# OpenTallas memory compiler (tools/mem_compiler), ASAP7 abstract view, track-aligned v2 (build_aligned_v2.py)
VERSION 5.7 ;
BUSBITCHARS "[]" ;
DIVIDERCHAR "/" ;
PROPERTYDEFINITIONS
  MACRO width INTEGER ;
  MACRO depth INTEGER ;
  MACRO banks INTEGER ;
END PROPERTYDEFINITIONS
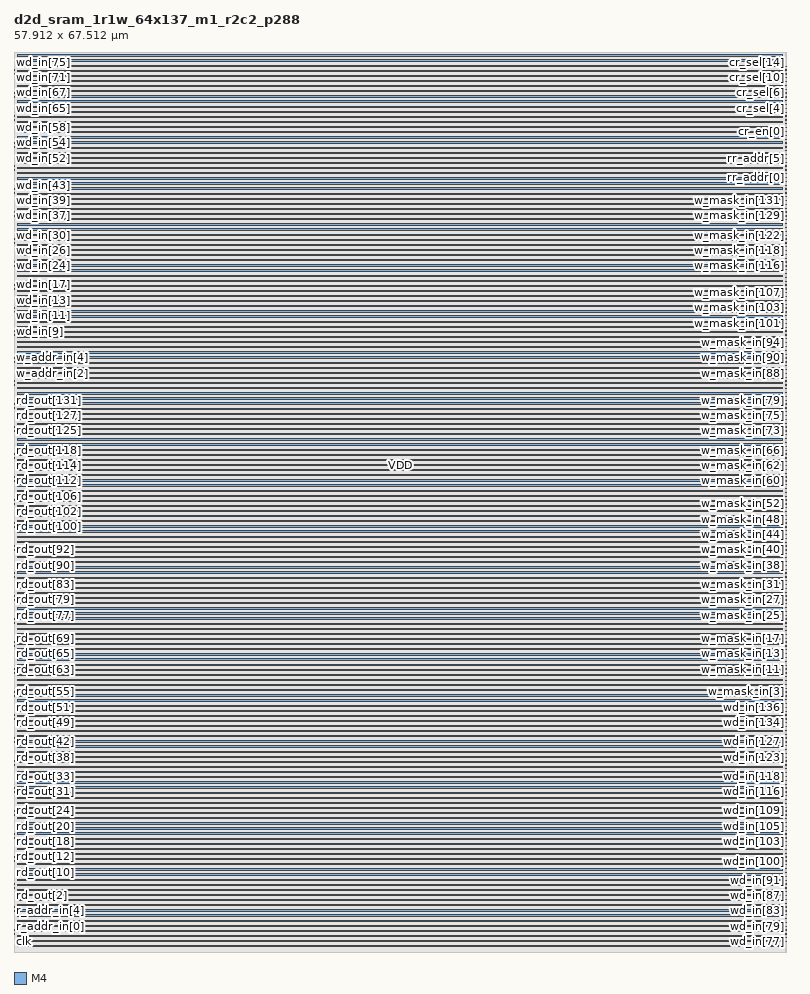
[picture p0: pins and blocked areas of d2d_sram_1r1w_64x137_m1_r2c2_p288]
MACRO d2d_sram_1r1w_64x137_m1_r2c2_p288
  PROPERTY width 137 ;
  PROPERTY depth 64 ;
  PROPERTY banks 1 ;
  FOREIGN d2d_sram_1r1w_64x137_m1_r2c2_p288 0 0 ;
  SYMMETRY X Y ;
  SIZE 57.912 BY 67.512 ;
  CLASS BLOCK ;
  PIN clk
    DIRECTION INPUT ;
    USE CLOCK ;
    SHAPE ABUTMENT ;
    PORT
      LAYER M4 ;
      RECT 0.000 0.768 0.024 0.792 ;
    END
  END clk
  PIN r_ce_in
    DIRECTION INPUT ;
    USE SIGNAL ;
    SHAPE ABUTMENT ;
    PORT
      LAYER M4 ;
      RECT 0.000 1.056 0.024 1.080 ;
    END
  END r_ce_in
  PIN r_addr_in[0]
    DIRECTION INPUT ;
    USE SIGNAL ;
    SHAPE ABUTMENT ;
    PORT
      LAYER M4 ;
      RECT 0.000 1.344 0.024 1.368 ;
    END
  END r_addr_in[0]
  PIN r_addr_in[1]
    DIRECTION INPUT ;
    USE SIGNAL ;
    SHAPE ABUTMENT ;
    PORT
      LAYER M4 ;
      RECT 0.000 1.632 0.024 1.656 ;
    END
  END r_addr_in[1]
  PIN r_addr_in[2]
    DIRECTION INPUT ;
    USE SIGNAL ;
    SHAPE ABUTMENT ;
    PORT
      LAYER M4 ;
      RECT 0.000 1.920 0.024 1.944 ;
    END
  END r_addr_in[2]
  PIN r_addr_in[3]
    DIRECTION INPUT ;
    USE SIGNAL ;
    SHAPE ABUTMENT ;
    PORT
      LAYER M4 ;
      RECT 0.000 2.208 0.024 2.232 ;
    END
  END r_addr_in[3]
  PIN r_addr_in[4]
    DIRECTION INPUT ;
    USE SIGNAL ;
    SHAPE ABUTMENT ;
    PORT
      LAYER M4 ;
      RECT 0.000 2.496 0.024 2.520 ;
    END
  END r_addr_in[4]
  PIN r_addr_in[5]
    DIRECTION INPUT ;
    USE SIGNAL ;
    SHAPE ABUTMENT ;
    PORT
      LAYER M4 ;
      RECT 0.000 2.784 0.024 2.808 ;
    END
  END r_addr_in[5]
  PIN rd_out[0]
    DIRECTION OUTPUT ;
    USE SIGNAL ;
    SHAPE ABUTMENT ;
    PORT
      LAYER M4 ;
      RECT 0.000 3.072 0.024 3.096 ;
    END
  END rd_out[0]
  PIN rd_out[1]
    DIRECTION OUTPUT ;
    USE SIGNAL ;
    SHAPE ABUTMENT ;
    PORT
      LAYER M4 ;
      RECT 0.000 3.360 0.024 3.384 ;
    END
  END rd_out[1]
  PIN rd_out[2]
    DIRECTION OUTPUT ;
    USE SIGNAL ;
    SHAPE ABUTMENT ;
    PORT
      LAYER M4 ;
      RECT 0.000 3.648 0.024 3.672 ;
    END
  END rd_out[2]
  PIN rd_out[3]
    DIRECTION OUTPUT ;
    USE SIGNAL ;
    SHAPE ABUTMENT ;
    PORT
      LAYER M4 ;
      RECT 0.000 3.936 0.024 3.960 ;
    END
  END rd_out[3]
  PIN rd_out[4]
    DIRECTION OUTPUT ;
    USE SIGNAL ;
    SHAPE ABUTMENT ;
    PORT
      LAYER M4 ;
      RECT 0.000 4.224 0.024 4.248 ;
    END
  END rd_out[4]
  PIN rd_out[5]
    DIRECTION OUTPUT ;
    USE SIGNAL ;
    SHAPE ABUTMENT ;
    PORT
      LAYER M4 ;
      RECT 0.000 4.512 0.024 4.536 ;
    END
  END rd_out[5]
  PIN rd_out[6]
    DIRECTION OUTPUT ;
    USE SIGNAL ;
    SHAPE ABUTMENT ;
    PORT
      LAYER M4 ;
      RECT 0.000 4.800 0.024 4.824 ;
    END
  END rd_out[6]
  PIN rd_out[7]
    DIRECTION OUTPUT ;
    USE SIGNAL ;
    SHAPE ABUTMENT ;
    PORT
      LAYER M4 ;
      RECT 0.000 5.088 0.024 5.112 ;
    END
  END rd_out[7]
  PIN rd_out[8]
    DIRECTION OUTPUT ;
    USE SIGNAL ;
    SHAPE ABUTMENT ;
    PORT
      LAYER M4 ;
      RECT 0.000 5.376 0.024 5.400 ;
    END
  END rd_out[8]
  PIN rd_out[9]
    DIRECTION OUTPUT ;
    USE SIGNAL ;
    SHAPE ABUTMENT ;
    PORT
      LAYER M4 ;
      RECT 0.000 5.664 0.024 5.688 ;
    END
  END rd_out[9]
  PIN rd_out[10]
    DIRECTION OUTPUT ;
    USE SIGNAL ;
    SHAPE ABUTMENT ;
    PORT
      LAYER M4 ;
      RECT 0.000 5.952 0.024 5.976 ;
    END
  END rd_out[10]
  PIN rd_out[11]
    DIRECTION OUTPUT ;
    USE SIGNAL ;
    SHAPE ABUTMENT ;
    PORT
      LAYER M4 ;
      RECT 0.000 6.240 0.024 6.264 ;
    END
  END rd_out[11]
  PIN rd_out[12]
    DIRECTION OUTPUT ;
    USE SIGNAL ;
    SHAPE ABUTMENT ;
    PORT
      LAYER M4 ;
      RECT 0.000 6.528 0.024 6.552 ;
    END
  END rd_out[12]
  PIN rd_out[13]
    DIRECTION OUTPUT ;
    USE SIGNAL ;
    SHAPE ABUTMENT ;
    PORT
      LAYER M4 ;
      RECT 0.000 6.816 0.024 6.840 ;
    END
  END rd_out[13]
  PIN rd_out[14]
    DIRECTION OUTPUT ;
    USE SIGNAL ;
    SHAPE ABUTMENT ;
    PORT
      LAYER M4 ;
      RECT 0.000 7.104 0.024 7.128 ;
    END
  END rd_out[14]
  PIN rd_out[15]
    DIRECTION OUTPUT ;
    USE SIGNAL ;
    SHAPE ABUTMENT ;
    PORT
      LAYER M4 ;
      RECT 0.000 7.392 0.024 7.416 ;
    END
  END rd_out[15]
  PIN rd_out[16]
    DIRECTION OUTPUT ;
    USE SIGNAL ;
    SHAPE ABUTMENT ;
    PORT
      LAYER M4 ;
      RECT 0.000 7.680 0.024 7.704 ;
    END
  END rd_out[16]
  PIN rd_out[17]
    DIRECTION OUTPUT ;
    USE SIGNAL ;
    SHAPE ABUTMENT ;
    PORT
      LAYER M4 ;
      RECT 0.000 7.968 0.024 7.992 ;
    END
  END rd_out[17]
  PIN rd_out[18]
    DIRECTION OUTPUT ;
    USE SIGNAL ;
    SHAPE ABUTMENT ;
    PORT
      LAYER M4 ;
      RECT 0.000 8.256 0.024 8.280 ;
    END
  END rd_out[18]
  PIN rd_out[19]
    DIRECTION OUTPUT ;
    USE SIGNAL ;
    SHAPE ABUTMENT ;
    PORT
      LAYER M4 ;
      RECT 0.000 8.544 0.024 8.568 ;
    END
  END rd_out[19]
  PIN rd_out[20]
    DIRECTION OUTPUT ;
    USE SIGNAL ;
    SHAPE ABUTMENT ;
    PORT
      LAYER M4 ;
      RECT 0.000 8.832 0.024 8.856 ;
    END
  END rd_out[20]
  PIN rd_out[21]
    DIRECTION OUTPUT ;
    USE SIGNAL ;
    SHAPE ABUTMENT ;
    PORT
      LAYER M4 ;
      RECT 0.000 9.120 0.024 9.144 ;
    END
  END rd_out[21]
  PIN rd_out[22]
    DIRECTION OUTPUT ;
    USE SIGNAL ;
    SHAPE ABUTMENT ;
    PORT
      LAYER M4 ;
      RECT 0.000 9.408 0.024 9.432 ;
    END
  END rd_out[22]
  PIN rd_out[23]
    DIRECTION OUTPUT ;
    USE SIGNAL ;
    SHAPE ABUTMENT ;
    PORT
      LAYER M4 ;
      RECT 0.000 9.696 0.024 9.720 ;
    END
  END rd_out[23]
  PIN rd_out[24]
    DIRECTION OUTPUT ;
    USE SIGNAL ;
    SHAPE ABUTMENT ;
    PORT
      LAYER M4 ;
      RECT 0.000 9.984 0.024 10.008 ;
    END
  END rd_out[24]
  PIN rd_out[25]
    DIRECTION OUTPUT ;
    USE SIGNAL ;
    SHAPE ABUTMENT ;
    PORT
      LAYER M4 ;
      RECT 0.000 10.272 0.024 10.296 ;
    END
  END rd_out[25]
  PIN rd_out[26]
    DIRECTION OUTPUT ;
    USE SIGNAL ;
    SHAPE ABUTMENT ;
    PORT
      LAYER M4 ;
      RECT 0.000 10.560 0.024 10.584 ;
    END
  END rd_out[26]
  PIN rd_out[27]
    DIRECTION OUTPUT ;
    USE SIGNAL ;
    SHAPE ABUTMENT ;
    PORT
      LAYER M4 ;
      RECT 0.000 10.848 0.024 10.872 ;
    END
  END rd_out[27]
  PIN rd_out[28]
    DIRECTION OUTPUT ;
    USE SIGNAL ;
    SHAPE ABUTMENT ;
    PORT
      LAYER M4 ;
      RECT 0.000 11.136 0.024 11.160 ;
    END
  END rd_out[28]
  PIN rd_out[29]
    DIRECTION OUTPUT ;
    USE SIGNAL ;
    SHAPE ABUTMENT ;
    PORT
      LAYER M4 ;
      RECT 0.000 11.424 0.024 11.448 ;
    END
  END rd_out[29]
  PIN rd_out[30]
    DIRECTION OUTPUT ;
    USE SIGNAL ;
    SHAPE ABUTMENT ;
    PORT
      LAYER M4 ;
      RECT 0.000 11.712 0.024 11.736 ;
    END
  END rd_out[30]
  PIN rd_out[31]
    DIRECTION OUTPUT ;
    USE SIGNAL ;
    SHAPE ABUTMENT ;
    PORT
      LAYER M4 ;
      RECT 0.000 12.000 0.024 12.024 ;
    END
  END rd_out[31]
  PIN rd_out[32]
    DIRECTION OUTPUT ;
    USE SIGNAL ;
    SHAPE ABUTMENT ;
    PORT
      LAYER M4 ;
      RECT 0.000 12.288 0.024 12.312 ;
    END
  END rd_out[32]
  PIN rd_out[33]
    DIRECTION OUTPUT ;
    USE SIGNAL ;
    SHAPE ABUTMENT ;
    PORT
      LAYER M4 ;
      RECT 0.000 12.576 0.024 12.600 ;
    END
  END rd_out[33]
  PIN rd_out[34]
    DIRECTION OUTPUT ;
    USE SIGNAL ;
    SHAPE ABUTMENT ;
    PORT
      LAYER M4 ;
      RECT 0.000 12.864 0.024 12.888 ;
    END
  END rd_out[34]
  PIN rd_out[35]
    DIRECTION OUTPUT ;
    USE SIGNAL ;
    SHAPE ABUTMENT ;
    PORT
      LAYER M4 ;
      RECT 0.000 13.152 0.024 13.176 ;
    END
  END rd_out[35]
  PIN rd_out[36]
    DIRECTION OUTPUT ;
    USE SIGNAL ;
    SHAPE ABUTMENT ;
    PORT
      LAYER M4 ;
      RECT 0.000 13.440 0.024 13.464 ;
    END
  END rd_out[36]
  PIN rd_out[37]
    DIRECTION OUTPUT ;
    USE SIGNAL ;
    SHAPE ABUTMENT ;
    PORT
      LAYER M4 ;
      RECT 0.000 13.728 0.024 13.752 ;
    END
  END rd_out[37]
  PIN rd_out[38]
    DIRECTION OUTPUT ;
    USE SIGNAL ;
    SHAPE ABUTMENT ;
    PORT
      LAYER M4 ;
      RECT 0.000 14.016 0.024 14.040 ;
    END
  END rd_out[38]
  PIN rd_out[39]
    DIRECTION OUTPUT ;
    USE SIGNAL ;
    SHAPE ABUTMENT ;
    PORT
      LAYER M4 ;
      RECT 0.000 14.304 0.024 14.328 ;
    END
  END rd_out[39]
  PIN rd_out[40]
    DIRECTION OUTPUT ;
    USE SIGNAL ;
    SHAPE ABUTMENT ;
    PORT
      LAYER M4 ;
      RECT 0.000 14.592 0.024 14.616 ;
    END
  END rd_out[40]
  PIN rd_out[41]
    DIRECTION OUTPUT ;
    USE SIGNAL ;
    SHAPE ABUTMENT ;
    PORT
      LAYER M4 ;
      RECT 0.000 14.880 0.024 14.904 ;
    END
  END rd_out[41]
  PIN rd_out[42]
    DIRECTION OUTPUT ;
    USE SIGNAL ;
    SHAPE ABUTMENT ;
    PORT
      LAYER M4 ;
      RECT 0.000 15.168 0.024 15.192 ;
    END
  END rd_out[42]
  PIN rd_out[43]
    DIRECTION OUTPUT ;
    USE SIGNAL ;
    SHAPE ABUTMENT ;
    PORT
      LAYER M4 ;
      RECT 0.000 15.456 0.024 15.480 ;
    END
  END rd_out[43]
  PIN rd_out[44]
    DIRECTION OUTPUT ;
    USE SIGNAL ;
    SHAPE ABUTMENT ;
    PORT
      LAYER M4 ;
      RECT 0.000 15.744 0.024 15.768 ;
    END
  END rd_out[44]
  PIN rd_out[45]
    DIRECTION OUTPUT ;
    USE SIGNAL ;
    SHAPE ABUTMENT ;
    PORT
      LAYER M4 ;
      RECT 0.000 16.032 0.024 16.056 ;
    END
  END rd_out[45]
  PIN rd_out[46]
    DIRECTION OUTPUT ;
    USE SIGNAL ;
    SHAPE ABUTMENT ;
    PORT
      LAYER M4 ;
      RECT 0.000 16.320 0.024 16.344 ;
    END
  END rd_out[46]
  PIN rd_out[47]
    DIRECTION OUTPUT ;
    USE SIGNAL ;
    SHAPE ABUTMENT ;
    PORT
      LAYER M4 ;
      RECT 0.000 16.608 0.024 16.632 ;
    END
  END rd_out[47]
  PIN rd_out[48]
    DIRECTION OUTPUT ;
    USE SIGNAL ;
    SHAPE ABUTMENT ;
    PORT
      LAYER M4 ;
      RECT 0.000 16.896 0.024 16.920 ;
    END
  END rd_out[48]
  PIN rd_out[49]
    DIRECTION OUTPUT ;
    USE SIGNAL ;
    SHAPE ABUTMENT ;
    PORT
      LAYER M4 ;
      RECT 0.000 17.184 0.024 17.208 ;
    END
  END rd_out[49]
  PIN rd_out[50]
    DIRECTION OUTPUT ;
    USE SIGNAL ;
    SHAPE ABUTMENT ;
    PORT
      LAYER M4 ;
      RECT 0.000 17.472 0.024 17.496 ;
    END
  END rd_out[50]
  PIN rd_out[51]
    DIRECTION OUTPUT ;
    USE SIGNAL ;
    SHAPE ABUTMENT ;
    PORT
      LAYER M4 ;
      RECT 0.000 17.760 0.024 17.784 ;
    END
  END rd_out[51]
  PIN rd_out[52]
    DIRECTION OUTPUT ;
    USE SIGNAL ;
    SHAPE ABUTMENT ;
    PORT
      LAYER M4 ;
      RECT 0.000 18.048 0.024 18.072 ;
    END
  END rd_out[52]
  PIN rd_out[53]
    DIRECTION OUTPUT ;
    USE SIGNAL ;
    SHAPE ABUTMENT ;
    PORT
      LAYER M4 ;
      RECT 0.000 18.336 0.024 18.360 ;
    END
  END rd_out[53]
  PIN rd_out[54]
    DIRECTION OUTPUT ;
    USE SIGNAL ;
    SHAPE ABUTMENT ;
    PORT
      LAYER M4 ;
      RECT 0.000 18.624 0.024 18.648 ;
    END
  END rd_out[54]
  PIN rd_out[55]
    DIRECTION OUTPUT ;
    USE SIGNAL ;
    SHAPE ABUTMENT ;
    PORT
      LAYER M4 ;
      RECT 0.000 18.912 0.024 18.936 ;
    END
  END rd_out[55]
  PIN rd_out[56]
    DIRECTION OUTPUT ;
    USE SIGNAL ;
    SHAPE ABUTMENT ;
    PORT
      LAYER M4 ;
      RECT 0.000 19.200 0.024 19.224 ;
    END
  END rd_out[56]
  PIN rd_out[57]
    DIRECTION OUTPUT ;
    USE SIGNAL ;
    SHAPE ABUTMENT ;
    PORT
      LAYER M4 ;
      RECT 0.000 19.488 0.024 19.512 ;
    END
  END rd_out[57]
  PIN rd_out[58]
    DIRECTION OUTPUT ;
    USE SIGNAL ;
    SHAPE ABUTMENT ;
    PORT
      LAYER M4 ;
      RECT 0.000 19.776 0.024 19.800 ;
    END
  END rd_out[58]
  PIN rd_out[59]
    DIRECTION OUTPUT ;
    USE SIGNAL ;
    SHAPE ABUTMENT ;
    PORT
      LAYER M4 ;
      RECT 0.000 20.064 0.024 20.088 ;
    END
  END rd_out[59]
  PIN rd_out[60]
    DIRECTION OUTPUT ;
    USE SIGNAL ;
    SHAPE ABUTMENT ;
    PORT
      LAYER M4 ;
      RECT 0.000 20.352 0.024 20.376 ;
    END
  END rd_out[60]
  PIN rd_out[61]
    DIRECTION OUTPUT ;
    USE SIGNAL ;
    SHAPE ABUTMENT ;
    PORT
      LAYER M4 ;
      RECT 0.000 20.640 0.024 20.664 ;
    END
  END rd_out[61]
  PIN rd_out[62]
    DIRECTION OUTPUT ;
    USE SIGNAL ;
    SHAPE ABUTMENT ;
    PORT
      LAYER M4 ;
      RECT 0.000 20.928 0.024 20.952 ;
    END
  END rd_out[62]
  PIN rd_out[63]
    DIRECTION OUTPUT ;
    USE SIGNAL ;
    SHAPE ABUTMENT ;
    PORT
      LAYER M4 ;
      RECT 0.000 21.216 0.024 21.240 ;
    END
  END rd_out[63]
  PIN rd_out[64]
    DIRECTION OUTPUT ;
    USE SIGNAL ;
    SHAPE ABUTMENT ;
    PORT
      LAYER M4 ;
      RECT 0.000 21.504 0.024 21.528 ;
    END
  END rd_out[64]
  PIN rd_out[65]
    DIRECTION OUTPUT ;
    USE SIGNAL ;
    SHAPE ABUTMENT ;
    PORT
      LAYER M4 ;
      RECT 0.000 21.792 0.024 21.816 ;
    END
  END rd_out[65]
  PIN rd_out[66]
    DIRECTION OUTPUT ;
    USE SIGNAL ;
    SHAPE ABUTMENT ;
    PORT
      LAYER M4 ;
      RECT 0.000 22.080 0.024 22.104 ;
    END
  END rd_out[66]
  PIN rd_out[67]
    DIRECTION OUTPUT ;
    USE SIGNAL ;
    SHAPE ABUTMENT ;
    PORT
      LAYER M4 ;
      RECT 0.000 22.368 0.024 22.392 ;
    END
  END rd_out[67]
  PIN rd_out[68]
    DIRECTION OUTPUT ;
    USE SIGNAL ;
    SHAPE ABUTMENT ;
    PORT
      LAYER M4 ;
      RECT 0.000 22.656 0.024 22.680 ;
    END
  END rd_out[68]
  PIN rd_out[69]
    DIRECTION OUTPUT ;
    USE SIGNAL ;
    SHAPE ABUTMENT ;
    PORT
      LAYER M4 ;
      RECT 0.000 22.944 0.024 22.968 ;
    END
  END rd_out[69]
  PIN rd_out[70]
    DIRECTION OUTPUT ;
    USE SIGNAL ;
    SHAPE ABUTMENT ;
    PORT
      LAYER M4 ;
      RECT 0.000 23.232 0.024 23.256 ;
    END
  END rd_out[70]
  PIN rd_out[71]
    DIRECTION OUTPUT ;
    USE SIGNAL ;
    SHAPE ABUTMENT ;
    PORT
      LAYER M4 ;
      RECT 0.000 23.520 0.024 23.544 ;
    END
  END rd_out[71]
  PIN rd_out[72]
    DIRECTION OUTPUT ;
    USE SIGNAL ;
    SHAPE ABUTMENT ;
    PORT
      LAYER M4 ;
      RECT 0.000 23.808 0.024 23.832 ;
    END
  END rd_out[72]
  PIN rd_out[73]
    DIRECTION OUTPUT ;
    USE SIGNAL ;
    SHAPE ABUTMENT ;
    PORT
      LAYER M4 ;
      RECT 0.000 24.096 0.024 24.120 ;
    END
  END rd_out[73]
  PIN rd_out[74]
    DIRECTION OUTPUT ;
    USE SIGNAL ;
    SHAPE ABUTMENT ;
    PORT
      LAYER M4 ;
      RECT 0.000 24.384 0.024 24.408 ;
    END
  END rd_out[74]
  PIN rd_out[75]
    DIRECTION OUTPUT ;
    USE SIGNAL ;
    SHAPE ABUTMENT ;
    PORT
      LAYER M4 ;
      RECT 0.000 24.672 0.024 24.696 ;
    END
  END rd_out[75]
  PIN rd_out[76]
    DIRECTION OUTPUT ;
    USE SIGNAL ;
    SHAPE ABUTMENT ;
    PORT
      LAYER M4 ;
      RECT 0.000 24.960 0.024 24.984 ;
    END
  END rd_out[76]
  PIN rd_out[77]
    DIRECTION OUTPUT ;
    USE SIGNAL ;
    SHAPE ABUTMENT ;
    PORT
      LAYER M4 ;
      RECT 0.000 25.248 0.024 25.272 ;
    END
  END rd_out[77]
  PIN rd_out[78]
    DIRECTION OUTPUT ;
    USE SIGNAL ;
    SHAPE ABUTMENT ;
    PORT
      LAYER M4 ;
      RECT 0.000 25.536 0.024 25.560 ;
    END
  END rd_out[78]
  PIN rd_out[79]
    DIRECTION OUTPUT ;
    USE SIGNAL ;
    SHAPE ABUTMENT ;
    PORT
      LAYER M4 ;
      RECT 0.000 25.824 0.024 25.848 ;
    END
  END rd_out[79]
  PIN rd_out[80]
    DIRECTION OUTPUT ;
    USE SIGNAL ;
    SHAPE ABUTMENT ;
    PORT
      LAYER M4 ;
      RECT 0.000 26.112 0.024 26.136 ;
    END
  END rd_out[80]
  PIN rd_out[81]
    DIRECTION OUTPUT ;
    USE SIGNAL ;
    SHAPE ABUTMENT ;
    PORT
      LAYER M4 ;
      RECT 0.000 26.400 0.024 26.424 ;
    END
  END rd_out[81]
  PIN rd_out[82]
    DIRECTION OUTPUT ;
    USE SIGNAL ;
    SHAPE ABUTMENT ;
    PORT
      LAYER M4 ;
      RECT 0.000 26.688 0.024 26.712 ;
    END
  END rd_out[82]
  PIN rd_out[83]
    DIRECTION OUTPUT ;
    USE SIGNAL ;
    SHAPE ABUTMENT ;
    PORT
      LAYER M4 ;
      RECT 0.000 26.976 0.024 27.000 ;
    END
  END rd_out[83]
  PIN rd_out[84]
    DIRECTION OUTPUT ;
    USE SIGNAL ;
    SHAPE ABUTMENT ;
    PORT
      LAYER M4 ;
      RECT 0.000 27.264 0.024 27.288 ;
    END
  END rd_out[84]
  PIN rd_out[85]
    DIRECTION OUTPUT ;
    USE SIGNAL ;
    SHAPE ABUTMENT ;
    PORT
      LAYER M4 ;
      RECT 0.000 27.552 0.024 27.576 ;
    END
  END rd_out[85]
  PIN rd_out[86]
    DIRECTION OUTPUT ;
    USE SIGNAL ;
    SHAPE ABUTMENT ;
    PORT
      LAYER M4 ;
      RECT 0.000 27.840 0.024 27.864 ;
    END
  END rd_out[86]
  PIN rd_out[87]
    DIRECTION OUTPUT ;
    USE SIGNAL ;
    SHAPE ABUTMENT ;
    PORT
      LAYER M4 ;
      RECT 0.000 28.128 0.024 28.152 ;
    END
  END rd_out[87]
  PIN rd_out[88]
    DIRECTION OUTPUT ;
    USE SIGNAL ;
    SHAPE ABUTMENT ;
    PORT
      LAYER M4 ;
      RECT 0.000 28.416 0.024 28.440 ;
    END
  END rd_out[88]
  PIN rd_out[89]
    DIRECTION OUTPUT ;
    USE SIGNAL ;
    SHAPE ABUTMENT ;
    PORT
      LAYER M4 ;
      RECT 0.000 28.704 0.024 28.728 ;
    END
  END rd_out[89]
  PIN rd_out[90]
    DIRECTION OUTPUT ;
    USE SIGNAL ;
    SHAPE ABUTMENT ;
    PORT
      LAYER M4 ;
      RECT 0.000 28.992 0.024 29.016 ;
    END
  END rd_out[90]
  PIN rd_out[91]
    DIRECTION OUTPUT ;
    USE SIGNAL ;
    SHAPE ABUTMENT ;
    PORT
      LAYER M4 ;
      RECT 0.000 29.280 0.024 29.304 ;
    END
  END rd_out[91]
  PIN rd_out[92]
    DIRECTION OUTPUT ;
    USE SIGNAL ;
    SHAPE ABUTMENT ;
    PORT
      LAYER M4 ;
      RECT 0.000 29.568 0.024 29.592 ;
    END
  END rd_out[92]
  PIN rd_out[93]
    DIRECTION OUTPUT ;
    USE SIGNAL ;
    SHAPE ABUTMENT ;
    PORT
      LAYER M4 ;
      RECT 0.000 29.856 0.024 29.880 ;
    END
  END rd_out[93]
  PIN rd_out[94]
    DIRECTION OUTPUT ;
    USE SIGNAL ;
    SHAPE ABUTMENT ;
    PORT
      LAYER M4 ;
      RECT 0.000 30.144 0.024 30.168 ;
    END
  END rd_out[94]
  PIN rd_out[95]
    DIRECTION OUTPUT ;
    USE SIGNAL ;
    SHAPE ABUTMENT ;
    PORT
      LAYER M4 ;
      RECT 0.000 30.432 0.024 30.456 ;
    END
  END rd_out[95]
  PIN rd_out[96]
    DIRECTION OUTPUT ;
    USE SIGNAL ;
    SHAPE ABUTMENT ;
    PORT
      LAYER M4 ;
      RECT 0.000 30.720 0.024 30.744 ;
    END
  END rd_out[96]
  PIN rd_out[97]
    DIRECTION OUTPUT ;
    USE SIGNAL ;
    SHAPE ABUTMENT ;
    PORT
      LAYER M4 ;
      RECT 0.000 31.008 0.024 31.032 ;
    END
  END rd_out[97]
  PIN rd_out[98]
    DIRECTION OUTPUT ;
    USE SIGNAL ;
    SHAPE ABUTMENT ;
    PORT
      LAYER M4 ;
      RECT 0.000 31.296 0.024 31.320 ;
    END
  END rd_out[98]
  PIN rd_out[99]
    DIRECTION OUTPUT ;
    USE SIGNAL ;
    SHAPE ABUTMENT ;
    PORT
      LAYER M4 ;
      RECT 0.000 31.584 0.024 31.608 ;
    END
  END rd_out[99]
  PIN rd_out[100]
    DIRECTION OUTPUT ;
    USE SIGNAL ;
    SHAPE ABUTMENT ;
    PORT
      LAYER M4 ;
      RECT 0.000 31.872 0.024 31.896 ;
    END
  END rd_out[100]
  PIN rd_out[101]
    DIRECTION OUTPUT ;
    USE SIGNAL ;
    SHAPE ABUTMENT ;
    PORT
      LAYER M4 ;
      RECT 0.000 32.160 0.024 32.184 ;
    END
  END rd_out[101]
  PIN rd_out[102]
    DIRECTION OUTPUT ;
    USE SIGNAL ;
    SHAPE ABUTMENT ;
    PORT
      LAYER M4 ;
      RECT 0.000 32.448 0.024 32.472 ;
    END
  END rd_out[102]
  PIN rd_out[103]
    DIRECTION OUTPUT ;
    USE SIGNAL ;
    SHAPE ABUTMENT ;
    PORT
      LAYER M4 ;
      RECT 0.000 32.736 0.024 32.760 ;
    END
  END rd_out[103]
  PIN rd_out[104]
    DIRECTION OUTPUT ;
    USE SIGNAL ;
    SHAPE ABUTMENT ;
    PORT
      LAYER M4 ;
      RECT 0.000 33.024 0.024 33.048 ;
    END
  END rd_out[104]
  PIN rd_out[105]
    DIRECTION OUTPUT ;
    USE SIGNAL ;
    SHAPE ABUTMENT ;
    PORT
      LAYER M4 ;
      RECT 0.000 33.312 0.024 33.336 ;
    END
  END rd_out[105]
  PIN rd_out[106]
    DIRECTION OUTPUT ;
    USE SIGNAL ;
    SHAPE ABUTMENT ;
    PORT
      LAYER M4 ;
      RECT 0.000 33.600 0.024 33.624 ;
    END
  END rd_out[106]
  PIN rd_out[107]
    DIRECTION OUTPUT ;
    USE SIGNAL ;
    SHAPE ABUTMENT ;
    PORT
      LAYER M4 ;
      RECT 0.000 33.888 0.024 33.912 ;
    END
  END rd_out[107]
  PIN rd_out[108]
    DIRECTION OUTPUT ;
    USE SIGNAL ;
    SHAPE ABUTMENT ;
    PORT
      LAYER M4 ;
      RECT 0.000 34.176 0.024 34.200 ;
    END
  END rd_out[108]
  PIN rd_out[109]
    DIRECTION OUTPUT ;
    USE SIGNAL ;
    SHAPE ABUTMENT ;
    PORT
      LAYER M4 ;
      RECT 0.000 34.464 0.024 34.488 ;
    END
  END rd_out[109]
  PIN rd_out[110]
    DIRECTION OUTPUT ;
    USE SIGNAL ;
    SHAPE ABUTMENT ;
    PORT
      LAYER M4 ;
      RECT 0.000 34.752 0.024 34.776 ;
    END
  END rd_out[110]
  PIN rd_out[111]
    DIRECTION OUTPUT ;
    USE SIGNAL ;
    SHAPE ABUTMENT ;
    PORT
      LAYER M4 ;
      RECT 0.000 35.040 0.024 35.064 ;
    END
  END rd_out[111]
  PIN rd_out[112]
    DIRECTION OUTPUT ;
    USE SIGNAL ;
    SHAPE ABUTMENT ;
    PORT
      LAYER M4 ;
      RECT 0.000 35.328 0.024 35.352 ;
    END
  END rd_out[112]
  PIN rd_out[113]
    DIRECTION OUTPUT ;
    USE SIGNAL ;
    SHAPE ABUTMENT ;
    PORT
      LAYER M4 ;
      RECT 0.000 35.616 0.024 35.640 ;
    END
  END rd_out[113]
  PIN rd_out[114]
    DIRECTION OUTPUT ;
    USE SIGNAL ;
    SHAPE ABUTMENT ;
    PORT
      LAYER M4 ;
      RECT 0.000 35.904 0.024 35.928 ;
    END
  END rd_out[114]
  PIN rd_out[115]
    DIRECTION OUTPUT ;
    USE SIGNAL ;
    SHAPE ABUTMENT ;
    PORT
      LAYER M4 ;
      RECT 0.000 36.192 0.024 36.216 ;
    END
  END rd_out[115]
  PIN rd_out[116]
    DIRECTION OUTPUT ;
    USE SIGNAL ;
    SHAPE ABUTMENT ;
    PORT
      LAYER M4 ;
      RECT 0.000 36.480 0.024 36.504 ;
    END
  END rd_out[116]
  PIN rd_out[117]
    DIRECTION OUTPUT ;
    USE SIGNAL ;
    SHAPE ABUTMENT ;
    PORT
      LAYER M4 ;
      RECT 0.000 36.768 0.024 36.792 ;
    END
  END rd_out[117]
  PIN rd_out[118]
    DIRECTION OUTPUT ;
    USE SIGNAL ;
    SHAPE ABUTMENT ;
    PORT
      LAYER M4 ;
      RECT 0.000 37.056 0.024 37.080 ;
    END
  END rd_out[118]
  PIN rd_out[119]
    DIRECTION OUTPUT ;
    USE SIGNAL ;
    SHAPE ABUTMENT ;
    PORT
      LAYER M4 ;
      RECT 0.000 37.344 0.024 37.368 ;
    END
  END rd_out[119]
  PIN rd_out[120]
    DIRECTION OUTPUT ;
    USE SIGNAL ;
    SHAPE ABUTMENT ;
    PORT
      LAYER M4 ;
      RECT 0.000 37.632 0.024 37.656 ;
    END
  END rd_out[120]
  PIN rd_out[121]
    DIRECTION OUTPUT ;
    USE SIGNAL ;
    SHAPE ABUTMENT ;
    PORT
      LAYER M4 ;
      RECT 0.000 37.920 0.024 37.944 ;
    END
  END rd_out[121]
  PIN rd_out[122]
    DIRECTION OUTPUT ;
    USE SIGNAL ;
    SHAPE ABUTMENT ;
    PORT
      LAYER M4 ;
      RECT 0.000 38.208 0.024 38.232 ;
    END
  END rd_out[122]
  PIN rd_out[123]
    DIRECTION OUTPUT ;
    USE SIGNAL ;
    SHAPE ABUTMENT ;
    PORT
      LAYER M4 ;
      RECT 0.000 38.496 0.024 38.520 ;
    END
  END rd_out[123]
  PIN rd_out[124]
    DIRECTION OUTPUT ;
    USE SIGNAL ;
    SHAPE ABUTMENT ;
    PORT
      LAYER M4 ;
      RECT 0.000 38.784 0.024 38.808 ;
    END
  END rd_out[124]
  PIN rd_out[125]
    DIRECTION OUTPUT ;
    USE SIGNAL ;
    SHAPE ABUTMENT ;
    PORT
      LAYER M4 ;
      RECT 0.000 39.072 0.024 39.096 ;
    END
  END rd_out[125]
  PIN rd_out[126]
    DIRECTION OUTPUT ;
    USE SIGNAL ;
    SHAPE ABUTMENT ;
    PORT
      LAYER M4 ;
      RECT 0.000 39.360 0.024 39.384 ;
    END
  END rd_out[126]
  PIN rd_out[127]
    DIRECTION OUTPUT ;
    USE SIGNAL ;
    SHAPE ABUTMENT ;
    PORT
      LAYER M4 ;
      RECT 0.000 39.648 0.024 39.672 ;
    END
  END rd_out[127]
  PIN rd_out[128]
    DIRECTION OUTPUT ;
    USE SIGNAL ;
    SHAPE ABUTMENT ;
    PORT
      LAYER M4 ;
      RECT 0.000 39.936 0.024 39.960 ;
    END
  END rd_out[128]
  PIN rd_out[129]
    DIRECTION OUTPUT ;
    USE SIGNAL ;
    SHAPE ABUTMENT ;
    PORT
      LAYER M4 ;
      RECT 0.000 40.224 0.024 40.248 ;
    END
  END rd_out[129]
  PIN rd_out[130]
    DIRECTION OUTPUT ;
    USE SIGNAL ;
    SHAPE ABUTMENT ;
    PORT
      LAYER M4 ;
      RECT 0.000 40.512 0.024 40.536 ;
    END
  END rd_out[130]
  PIN rd_out[131]
    DIRECTION OUTPUT ;
    USE SIGNAL ;
    SHAPE ABUTMENT ;
    PORT
      LAYER M4 ;
      RECT 0.000 40.800 0.024 40.824 ;
    END
  END rd_out[131]
  PIN rd_out[132]
    DIRECTION OUTPUT ;
    USE SIGNAL ;
    SHAPE ABUTMENT ;
    PORT
      LAYER M4 ;
      RECT 0.000 41.088 0.024 41.112 ;
    END
  END rd_out[132]
  PIN rd_out[133]
    DIRECTION OUTPUT ;
    USE SIGNAL ;
    SHAPE ABUTMENT ;
    PORT
      LAYER M4 ;
      RECT 0.000 41.376 0.024 41.400 ;
    END
  END rd_out[133]
  PIN rd_out[134]
    DIRECTION OUTPUT ;
    USE SIGNAL ;
    SHAPE ABUTMENT ;
    PORT
      LAYER M4 ;
      RECT 0.000 41.664 0.024 41.688 ;
    END
  END rd_out[134]
  PIN rd_out[135]
    DIRECTION OUTPUT ;
    USE SIGNAL ;
    SHAPE ABUTMENT ;
    PORT
      LAYER M4 ;
      RECT 0.000 41.952 0.024 41.976 ;
    END
  END rd_out[135]
  PIN rd_out[136]
    DIRECTION OUTPUT ;
    USE SIGNAL ;
    SHAPE ABUTMENT ;
    PORT
      LAYER M4 ;
      RECT 0.000 42.240 0.024 42.264 ;
    END
  END rd_out[136]
  PIN w_ce_in
    DIRECTION INPUT ;
    USE SIGNAL ;
    SHAPE ABUTMENT ;
    PORT
      LAYER M4 ;
      RECT 0.000 42.528 0.024 42.552 ;
    END
  END w_ce_in
  PIN w_addr_in[0]
    DIRECTION INPUT ;
    USE SIGNAL ;
    SHAPE ABUTMENT ;
    PORT
      LAYER M4 ;
      RECT 0.000 42.816 0.024 42.840 ;
    END
  END w_addr_in[0]
  PIN w_addr_in[1]
    DIRECTION INPUT ;
    USE SIGNAL ;
    SHAPE ABUTMENT ;
    PORT
      LAYER M4 ;
      RECT 0.000 43.104 0.024 43.128 ;
    END
  END w_addr_in[1]
  PIN w_addr_in[2]
    DIRECTION INPUT ;
    USE SIGNAL ;
    SHAPE ABUTMENT ;
    PORT
      LAYER M4 ;
      RECT 0.000 43.392 0.024 43.416 ;
    END
  END w_addr_in[2]
  PIN w_addr_in[3]
    DIRECTION INPUT ;
    USE SIGNAL ;
    SHAPE ABUTMENT ;
    PORT
      LAYER M4 ;
      RECT 0.000 43.680 0.024 43.704 ;
    END
  END w_addr_in[3]
  PIN w_addr_in[4]
    DIRECTION INPUT ;
    USE SIGNAL ;
    SHAPE ABUTMENT ;
    PORT
      LAYER M4 ;
      RECT 0.000 43.968 0.024 43.992 ;
    END
  END w_addr_in[4]
  PIN w_addr_in[5]
    DIRECTION INPUT ;
    USE SIGNAL ;
    SHAPE ABUTMENT ;
    PORT
      LAYER M4 ;
      RECT 0.000 44.256 0.024 44.280 ;
    END
  END w_addr_in[5]
  PIN wd_in[0]
    DIRECTION INPUT ;
    USE SIGNAL ;
    SHAPE ABUTMENT ;
    PORT
      LAYER M4 ;
      RECT 0.000 44.544 0.024 44.568 ;
    END
  END wd_in[0]
  PIN wd_in[1]
    DIRECTION INPUT ;
    USE SIGNAL ;
    SHAPE ABUTMENT ;
    PORT
      LAYER M4 ;
      RECT 0.000 44.832 0.024 44.856 ;
    END
  END wd_in[1]
  PIN wd_in[2]
    DIRECTION INPUT ;
    USE SIGNAL ;
    SHAPE ABUTMENT ;
    PORT
      LAYER M4 ;
      RECT 0.000 45.120 0.024 45.144 ;
    END
  END wd_in[2]
  PIN wd_in[3]
    DIRECTION INPUT ;
    USE SIGNAL ;
    SHAPE ABUTMENT ;
    PORT
      LAYER M4 ;
      RECT 0.000 45.408 0.024 45.432 ;
    END
  END wd_in[3]
  PIN wd_in[4]
    DIRECTION INPUT ;
    USE SIGNAL ;
    SHAPE ABUTMENT ;
    PORT
      LAYER M4 ;
      RECT 0.000 45.696 0.024 45.720 ;
    END
  END wd_in[4]
  PIN wd_in[5]
    DIRECTION INPUT ;
    USE SIGNAL ;
    SHAPE ABUTMENT ;
    PORT
      LAYER M4 ;
      RECT 0.000 45.984 0.024 46.008 ;
    END
  END wd_in[5]
  PIN wd_in[6]
    DIRECTION INPUT ;
    USE SIGNAL ;
    SHAPE ABUTMENT ;
    PORT
      LAYER M4 ;
      RECT 0.000 46.272 0.024 46.296 ;
    END
  END wd_in[6]
  PIN wd_in[7]
    DIRECTION INPUT ;
    USE SIGNAL ;
    SHAPE ABUTMENT ;
    PORT
      LAYER M4 ;
      RECT 0.000 46.560 0.024 46.584 ;
    END
  END wd_in[7]
  PIN wd_in[8]
    DIRECTION INPUT ;
    USE SIGNAL ;
    SHAPE ABUTMENT ;
    PORT
      LAYER M4 ;
      RECT 0.000 46.848 0.024 46.872 ;
    END
  END wd_in[8]
  PIN wd_in[9]
    DIRECTION INPUT ;
    USE SIGNAL ;
    SHAPE ABUTMENT ;
    PORT
      LAYER M4 ;
      RECT 0.000 47.136 0.024 47.160 ;
    END
  END wd_in[9]
  PIN wd_in[10]
    DIRECTION INPUT ;
    USE SIGNAL ;
    SHAPE ABUTMENT ;
    PORT
      LAYER M4 ;
      RECT 0.000 47.424 0.024 47.448 ;
    END
  END wd_in[10]
  PIN wd_in[11]
    DIRECTION INPUT ;
    USE SIGNAL ;
    SHAPE ABUTMENT ;
    PORT
      LAYER M4 ;
      RECT 0.000 47.712 0.024 47.736 ;
    END
  END wd_in[11]
  PIN wd_in[12]
    DIRECTION INPUT ;
    USE SIGNAL ;
    SHAPE ABUTMENT ;
    PORT
      LAYER M4 ;
      RECT 0.000 48.000 0.024 48.024 ;
    END
  END wd_in[12]
  PIN wd_in[13]
    DIRECTION INPUT ;
    USE SIGNAL ;
    SHAPE ABUTMENT ;
    PORT
      LAYER M4 ;
      RECT 0.000 48.288 0.024 48.312 ;
    END
  END wd_in[13]
  PIN wd_in[14]
    DIRECTION INPUT ;
    USE SIGNAL ;
    SHAPE ABUTMENT ;
    PORT
      LAYER M4 ;
      RECT 0.000 48.576 0.024 48.600 ;
    END
  END wd_in[14]
  PIN wd_in[15]
    DIRECTION INPUT ;
    USE SIGNAL ;
    SHAPE ABUTMENT ;
    PORT
      LAYER M4 ;
      RECT 0.000 48.864 0.024 48.888 ;
    END
  END wd_in[15]
  PIN wd_in[16]
    DIRECTION INPUT ;
    USE SIGNAL ;
    SHAPE ABUTMENT ;
    PORT
      LAYER M4 ;
      RECT 0.000 49.152 0.024 49.176 ;
    END
  END wd_in[16]
  PIN wd_in[17]
    DIRECTION INPUT ;
    USE SIGNAL ;
    SHAPE ABUTMENT ;
    PORT
      LAYER M4 ;
      RECT 0.000 49.440 0.024 49.464 ;
    END
  END wd_in[17]
  PIN wd_in[18]
    DIRECTION INPUT ;
    USE SIGNAL ;
    SHAPE ABUTMENT ;
    PORT
      LAYER M4 ;
      RECT 0.000 49.728 0.024 49.752 ;
    END
  END wd_in[18]
  PIN wd_in[19]
    DIRECTION INPUT ;
    USE SIGNAL ;
    SHAPE ABUTMENT ;
    PORT
      LAYER M4 ;
      RECT 0.000 50.016 0.024 50.040 ;
    END
  END wd_in[19]
  PIN wd_in[20]
    DIRECTION INPUT ;
    USE SIGNAL ;
    SHAPE ABUTMENT ;
    PORT
      LAYER M4 ;
      RECT 0.000 50.304 0.024 50.328 ;
    END
  END wd_in[20]
  PIN wd_in[21]
    DIRECTION INPUT ;
    USE SIGNAL ;
    SHAPE ABUTMENT ;
    PORT
      LAYER M4 ;
      RECT 0.000 50.592 0.024 50.616 ;
    END
  END wd_in[21]
  PIN wd_in[22]
    DIRECTION INPUT ;
    USE SIGNAL ;
    SHAPE ABUTMENT ;
    PORT
      LAYER M4 ;
      RECT 0.000 50.880 0.024 50.904 ;
    END
  END wd_in[22]
  PIN wd_in[23]
    DIRECTION INPUT ;
    USE SIGNAL ;
    SHAPE ABUTMENT ;
    PORT
      LAYER M4 ;
      RECT 0.000 51.168 0.024 51.192 ;
    END
  END wd_in[23]
  PIN wd_in[24]
    DIRECTION INPUT ;
    USE SIGNAL ;
    SHAPE ABUTMENT ;
    PORT
      LAYER M4 ;
      RECT 0.000 51.456 0.024 51.480 ;
    END
  END wd_in[24]
  PIN wd_in[25]
    DIRECTION INPUT ;
    USE SIGNAL ;
    SHAPE ABUTMENT ;
    PORT
      LAYER M4 ;
      RECT 0.000 51.744 0.024 51.768 ;
    END
  END wd_in[25]
  PIN wd_in[26]
    DIRECTION INPUT ;
    USE SIGNAL ;
    SHAPE ABUTMENT ;
    PORT
      LAYER M4 ;
      RECT 0.000 52.032 0.024 52.056 ;
    END
  END wd_in[26]
  PIN wd_in[27]
    DIRECTION INPUT ;
    USE SIGNAL ;
    SHAPE ABUTMENT ;
    PORT
      LAYER M4 ;
      RECT 0.000 52.320 0.024 52.344 ;
    END
  END wd_in[27]
  PIN wd_in[28]
    DIRECTION INPUT ;
    USE SIGNAL ;
    SHAPE ABUTMENT ;
    PORT
      LAYER M4 ;
      RECT 0.000 52.608 0.024 52.632 ;
    END
  END wd_in[28]
  PIN wd_in[29]
    DIRECTION INPUT ;
    USE SIGNAL ;
    SHAPE ABUTMENT ;
    PORT
      LAYER M4 ;
      RECT 0.000 52.896 0.024 52.920 ;
    END
  END wd_in[29]
  PIN wd_in[30]
    DIRECTION INPUT ;
    USE SIGNAL ;
    SHAPE ABUTMENT ;
    PORT
      LAYER M4 ;
      RECT 0.000 53.184 0.024 53.208 ;
    END
  END wd_in[30]
  PIN wd_in[31]
    DIRECTION INPUT ;
    USE SIGNAL ;
    SHAPE ABUTMENT ;
    PORT
      LAYER M4 ;
      RECT 0.000 53.472 0.024 53.496 ;
    END
  END wd_in[31]
  PIN wd_in[32]
    DIRECTION INPUT ;
    USE SIGNAL ;
    SHAPE ABUTMENT ;
    PORT
      LAYER M4 ;
      RECT 0.000 53.760 0.024 53.784 ;
    END
  END wd_in[32]
  PIN wd_in[33]
    DIRECTION INPUT ;
    USE SIGNAL ;
    SHAPE ABUTMENT ;
    PORT
      LAYER M4 ;
      RECT 0.000 54.048 0.024 54.072 ;
    END
  END wd_in[33]
  PIN wd_in[34]
    DIRECTION INPUT ;
    USE SIGNAL ;
    SHAPE ABUTMENT ;
    PORT
      LAYER M4 ;
      RECT 0.000 54.336 0.024 54.360 ;
    END
  END wd_in[34]
  PIN wd_in[35]
    DIRECTION INPUT ;
    USE SIGNAL ;
    SHAPE ABUTMENT ;
    PORT
      LAYER M4 ;
      RECT 0.000 54.624 0.024 54.648 ;
    END
  END wd_in[35]
  PIN wd_in[36]
    DIRECTION INPUT ;
    USE SIGNAL ;
    SHAPE ABUTMENT ;
    PORT
      LAYER M4 ;
      RECT 0.000 54.912 0.024 54.936 ;
    END
  END wd_in[36]
  PIN wd_in[37]
    DIRECTION INPUT ;
    USE SIGNAL ;
    SHAPE ABUTMENT ;
    PORT
      LAYER M4 ;
      RECT 0.000 55.200 0.024 55.224 ;
    END
  END wd_in[37]
  PIN wd_in[38]
    DIRECTION INPUT ;
    USE SIGNAL ;
    SHAPE ABUTMENT ;
    PORT
      LAYER M4 ;
      RECT 0.000 55.488 0.024 55.512 ;
    END
  END wd_in[38]
  PIN wd_in[39]
    DIRECTION INPUT ;
    USE SIGNAL ;
    SHAPE ABUTMENT ;
    PORT
      LAYER M4 ;
      RECT 0.000 55.776 0.024 55.800 ;
    END
  END wd_in[39]
  PIN wd_in[40]
    DIRECTION INPUT ;
    USE SIGNAL ;
    SHAPE ABUTMENT ;
    PORT
      LAYER M4 ;
      RECT 0.000 56.064 0.024 56.088 ;
    END
  END wd_in[40]
  PIN wd_in[41]
    DIRECTION INPUT ;
    USE SIGNAL ;
    SHAPE ABUTMENT ;
    PORT
      LAYER M4 ;
      RECT 0.000 56.352 0.024 56.376 ;
    END
  END wd_in[41]
  PIN wd_in[42]
    DIRECTION INPUT ;
    USE SIGNAL ;
    SHAPE ABUTMENT ;
    PORT
      LAYER M4 ;
      RECT 0.000 56.640 0.024 56.664 ;
    END
  END wd_in[42]
  PIN wd_in[43]
    DIRECTION INPUT ;
    USE SIGNAL ;
    SHAPE ABUTMENT ;
    PORT
      LAYER M4 ;
      RECT 0.000 56.928 0.024 56.952 ;
    END
  END wd_in[43]
  PIN wd_in[44]
    DIRECTION INPUT ;
    USE SIGNAL ;
    SHAPE ABUTMENT ;
    PORT
      LAYER M4 ;
      RECT 0.000 57.216 0.024 57.240 ;
    END
  END wd_in[44]
  PIN wd_in[45]
    DIRECTION INPUT ;
    USE SIGNAL ;
    SHAPE ABUTMENT ;
    PORT
      LAYER M4 ;
      RECT 0.000 57.504 0.024 57.528 ;
    END
  END wd_in[45]
  PIN wd_in[46]
    DIRECTION INPUT ;
    USE SIGNAL ;
    SHAPE ABUTMENT ;
    PORT
      LAYER M4 ;
      RECT 0.000 57.792 0.024 57.816 ;
    END
  END wd_in[46]
  PIN wd_in[47]
    DIRECTION INPUT ;
    USE SIGNAL ;
    SHAPE ABUTMENT ;
    PORT
      LAYER M4 ;
      RECT 0.000 58.080 0.024 58.104 ;
    END
  END wd_in[47]
  PIN wd_in[48]
    DIRECTION INPUT ;
    USE SIGNAL ;
    SHAPE ABUTMENT ;
    PORT
      LAYER M4 ;
      RECT 0.000 58.368 0.024 58.392 ;
    END
  END wd_in[48]
  PIN wd_in[49]
    DIRECTION INPUT ;
    USE SIGNAL ;
    SHAPE ABUTMENT ;
    PORT
      LAYER M4 ;
      RECT 0.000 58.656 0.024 58.680 ;
    END
  END wd_in[49]
  PIN wd_in[50]
    DIRECTION INPUT ;
    USE SIGNAL ;
    SHAPE ABUTMENT ;
    PORT
      LAYER M4 ;
      RECT 0.000 58.944 0.024 58.968 ;
    END
  END wd_in[50]
  PIN wd_in[51]
    DIRECTION INPUT ;
    USE SIGNAL ;
    SHAPE ABUTMENT ;
    PORT
      LAYER M4 ;
      RECT 0.000 59.232 0.024 59.256 ;
    END
  END wd_in[51]
  PIN wd_in[52]
    DIRECTION INPUT ;
    USE SIGNAL ;
    SHAPE ABUTMENT ;
    PORT
      LAYER M4 ;
      RECT 0.000 59.520 0.024 59.544 ;
    END
  END wd_in[52]
  PIN wd_in[53]
    DIRECTION INPUT ;
    USE SIGNAL ;
    SHAPE ABUTMENT ;
    PORT
      LAYER M4 ;
      RECT 0.000 59.808 0.024 59.832 ;
    END
  END wd_in[53]
  PIN wd_in[54]
    DIRECTION INPUT ;
    USE SIGNAL ;
    SHAPE ABUTMENT ;
    PORT
      LAYER M4 ;
      RECT 0.000 60.096 0.024 60.120 ;
    END
  END wd_in[54]
  PIN wd_in[55]
    DIRECTION INPUT ;
    USE SIGNAL ;
    SHAPE ABUTMENT ;
    PORT
      LAYER M4 ;
      RECT 0.000 60.384 0.024 60.408 ;
    END
  END wd_in[55]
  PIN wd_in[56]
    DIRECTION INPUT ;
    USE SIGNAL ;
    SHAPE ABUTMENT ;
    PORT
      LAYER M4 ;
      RECT 0.000 60.672 0.024 60.696 ;
    END
  END wd_in[56]
  PIN wd_in[57]
    DIRECTION INPUT ;
    USE SIGNAL ;
    SHAPE ABUTMENT ;
    PORT
      LAYER M4 ;
      RECT 0.000 60.960 0.024 60.984 ;
    END
  END wd_in[57]
  PIN wd_in[58]
    DIRECTION INPUT ;
    USE SIGNAL ;
    SHAPE ABUTMENT ;
    PORT
      LAYER M4 ;
      RECT 0.000 61.248 0.024 61.272 ;
    END
  END wd_in[58]
  PIN wd_in[59]
    DIRECTION INPUT ;
    USE SIGNAL ;
    SHAPE ABUTMENT ;
    PORT
      LAYER M4 ;
      RECT 0.000 61.536 0.024 61.560 ;
    END
  END wd_in[59]
  PIN wd_in[60]
    DIRECTION INPUT ;
    USE SIGNAL ;
    SHAPE ABUTMENT ;
    PORT
      LAYER M4 ;
      RECT 0.000 61.824 0.024 61.848 ;
    END
  END wd_in[60]
  PIN wd_in[61]
    DIRECTION INPUT ;
    USE SIGNAL ;
    SHAPE ABUTMENT ;
    PORT
      LAYER M4 ;
      RECT 0.000 62.112 0.024 62.136 ;
    END
  END wd_in[61]
  PIN wd_in[62]
    DIRECTION INPUT ;
    USE SIGNAL ;
    SHAPE ABUTMENT ;
    PORT
      LAYER M4 ;
      RECT 0.000 62.400 0.024 62.424 ;
    END
  END wd_in[62]
  PIN wd_in[63]
    DIRECTION INPUT ;
    USE SIGNAL ;
    SHAPE ABUTMENT ;
    PORT
      LAYER M4 ;
      RECT 0.000 62.688 0.024 62.712 ;
    END
  END wd_in[63]
  PIN wd_in[64]
    DIRECTION INPUT ;
    USE SIGNAL ;
    SHAPE ABUTMENT ;
    PORT
      LAYER M4 ;
      RECT 0.000 62.976 0.024 63.000 ;
    END
  END wd_in[64]
  PIN wd_in[65]
    DIRECTION INPUT ;
    USE SIGNAL ;
    SHAPE ABUTMENT ;
    PORT
      LAYER M4 ;
      RECT 0.000 63.264 0.024 63.288 ;
    END
  END wd_in[65]
  PIN wd_in[66]
    DIRECTION INPUT ;
    USE SIGNAL ;
    SHAPE ABUTMENT ;
    PORT
      LAYER M4 ;
      RECT 0.000 63.552 0.024 63.576 ;
    END
  END wd_in[66]
  PIN wd_in[67]
    DIRECTION INPUT ;
    USE SIGNAL ;
    SHAPE ABUTMENT ;
    PORT
      LAYER M4 ;
      RECT 0.000 63.840 0.024 63.864 ;
    END
  END wd_in[67]
  PIN wd_in[68]
    DIRECTION INPUT ;
    USE SIGNAL ;
    SHAPE ABUTMENT ;
    PORT
      LAYER M4 ;
      RECT 0.000 64.128 0.024 64.152 ;
    END
  END wd_in[68]
  PIN wd_in[69]
    DIRECTION INPUT ;
    USE SIGNAL ;
    SHAPE ABUTMENT ;
    PORT
      LAYER M4 ;
      RECT 0.000 64.416 0.024 64.440 ;
    END
  END wd_in[69]
  PIN wd_in[70]
    DIRECTION INPUT ;
    USE SIGNAL ;
    SHAPE ABUTMENT ;
    PORT
      LAYER M4 ;
      RECT 0.000 64.704 0.024 64.728 ;
    END
  END wd_in[70]
  PIN wd_in[71]
    DIRECTION INPUT ;
    USE SIGNAL ;
    SHAPE ABUTMENT ;
    PORT
      LAYER M4 ;
      RECT 0.000 64.992 0.024 65.016 ;
    END
  END wd_in[71]
  PIN wd_in[72]
    DIRECTION INPUT ;
    USE SIGNAL ;
    SHAPE ABUTMENT ;
    PORT
      LAYER M4 ;
      RECT 0.000 65.280 0.024 65.304 ;
    END
  END wd_in[72]
  PIN wd_in[73]
    DIRECTION INPUT ;
    USE SIGNAL ;
    SHAPE ABUTMENT ;
    PORT
      LAYER M4 ;
      RECT 0.000 65.568 0.024 65.592 ;
    END
  END wd_in[73]
  PIN wd_in[74]
    DIRECTION INPUT ;
    USE SIGNAL ;
    SHAPE ABUTMENT ;
    PORT
      LAYER M4 ;
      RECT 0.000 65.856 0.024 65.880 ;
    END
  END wd_in[74]
  PIN wd_in[75]
    DIRECTION INPUT ;
    USE SIGNAL ;
    SHAPE ABUTMENT ;
    PORT
      LAYER M4 ;
      RECT 0.000 66.144 0.024 66.168 ;
    END
  END wd_in[75]
  PIN wd_in[76]
    DIRECTION INPUT ;
    USE SIGNAL ;
    SHAPE ABUTMENT ;
    PORT
      LAYER M4 ;
      RECT 0.000 66.432 0.024 66.456 ;
    END
  END wd_in[76]
  PIN wd_in[77]
    DIRECTION INPUT ;
    USE SIGNAL ;
    SHAPE ABUTMENT ;
    PORT
      LAYER M4 ;
      RECT 57.888 0.768 57.912 0.792 ;
    END
  END wd_in[77]
  PIN wd_in[78]
    DIRECTION INPUT ;
    USE SIGNAL ;
    SHAPE ABUTMENT ;
    PORT
      LAYER M4 ;
      RECT 57.888 1.056 57.912 1.080 ;
    END
  END wd_in[78]
  PIN wd_in[79]
    DIRECTION INPUT ;
    USE SIGNAL ;
    SHAPE ABUTMENT ;
    PORT
      LAYER M4 ;
      RECT 57.888 1.344 57.912 1.368 ;
    END
  END wd_in[79]
  PIN wd_in[80]
    DIRECTION INPUT ;
    USE SIGNAL ;
    SHAPE ABUTMENT ;
    PORT
      LAYER M4 ;
      RECT 57.888 1.632 57.912 1.656 ;
    END
  END wd_in[80]
  PIN wd_in[81]
    DIRECTION INPUT ;
    USE SIGNAL ;
    SHAPE ABUTMENT ;
    PORT
      LAYER M4 ;
      RECT 57.888 1.920 57.912 1.944 ;
    END
  END wd_in[81]
  PIN wd_in[82]
    DIRECTION INPUT ;
    USE SIGNAL ;
    SHAPE ABUTMENT ;
    PORT
      LAYER M4 ;
      RECT 57.888 2.208 57.912 2.232 ;
    END
  END wd_in[82]
  PIN wd_in[83]
    DIRECTION INPUT ;
    USE SIGNAL ;
    SHAPE ABUTMENT ;
    PORT
      LAYER M4 ;
      RECT 57.888 2.496 57.912 2.520 ;
    END
  END wd_in[83]
  PIN wd_in[84]
    DIRECTION INPUT ;
    USE SIGNAL ;
    SHAPE ABUTMENT ;
    PORT
      LAYER M4 ;
      RECT 57.888 2.784 57.912 2.808 ;
    END
  END wd_in[84]
  PIN wd_in[85]
    DIRECTION INPUT ;
    USE SIGNAL ;
    SHAPE ABUTMENT ;
    PORT
      LAYER M4 ;
      RECT 57.888 3.072 57.912 3.096 ;
    END
  END wd_in[85]
  PIN wd_in[86]
    DIRECTION INPUT ;
    USE SIGNAL ;
    SHAPE ABUTMENT ;
    PORT
      LAYER M4 ;
      RECT 57.888 3.360 57.912 3.384 ;
    END
  END wd_in[86]
  PIN wd_in[87]
    DIRECTION INPUT ;
    USE SIGNAL ;
    SHAPE ABUTMENT ;
    PORT
      LAYER M4 ;
      RECT 57.888 3.648 57.912 3.672 ;
    END
  END wd_in[87]
  PIN wd_in[88]
    DIRECTION INPUT ;
    USE SIGNAL ;
    SHAPE ABUTMENT ;
    PORT
      LAYER M4 ;
      RECT 57.888 3.936 57.912 3.960 ;
    END
  END wd_in[88]
  PIN wd_in[89]
    DIRECTION INPUT ;
    USE SIGNAL ;
    SHAPE ABUTMENT ;
    PORT
      LAYER M4 ;
      RECT 57.888 4.224 57.912 4.248 ;
    END
  END wd_in[89]
  PIN wd_in[90]
    DIRECTION INPUT ;
    USE SIGNAL ;
    SHAPE ABUTMENT ;
    PORT
      LAYER M4 ;
      RECT 57.888 4.512 57.912 4.536 ;
    END
  END wd_in[90]
  PIN wd_in[91]
    DIRECTION INPUT ;
    USE SIGNAL ;
    SHAPE ABUTMENT ;
    PORT
      LAYER M4 ;
      RECT 57.888 4.800 57.912 4.824 ;
    END
  END wd_in[91]
  PIN wd_in[92]
    DIRECTION INPUT ;
    USE SIGNAL ;
    SHAPE ABUTMENT ;
    PORT
      LAYER M4 ;
      RECT 57.888 5.088 57.912 5.112 ;
    END
  END wd_in[92]
  PIN wd_in[93]
    DIRECTION INPUT ;
    USE SIGNAL ;
    SHAPE ABUTMENT ;
    PORT
      LAYER M4 ;
      RECT 57.888 5.376 57.912 5.400 ;
    END
  END wd_in[93]
  PIN wd_in[94]
    DIRECTION INPUT ;
    USE SIGNAL ;
    SHAPE ABUTMENT ;
    PORT
      LAYER M4 ;
      RECT 57.888 5.664 57.912 5.688 ;
    END
  END wd_in[94]
  PIN wd_in[95]
    DIRECTION INPUT ;
    USE SIGNAL ;
    SHAPE ABUTMENT ;
    PORT
      LAYER M4 ;
      RECT 57.888 5.952 57.912 5.976 ;
    END
  END wd_in[95]
  PIN wd_in[96]
    DIRECTION INPUT ;
    USE SIGNAL ;
    SHAPE ABUTMENT ;
    PORT
      LAYER M4 ;
      RECT 57.888 6.240 57.912 6.264 ;
    END
  END wd_in[96]
  PIN wd_in[97]
    DIRECTION INPUT ;
    USE SIGNAL ;
    SHAPE ABUTMENT ;
    PORT
      LAYER M4 ;
      RECT 57.888 6.528 57.912 6.552 ;
    END
  END wd_in[97]
  PIN wd_in[98]
    DIRECTION INPUT ;
    USE SIGNAL ;
    SHAPE ABUTMENT ;
    PORT
      LAYER M4 ;
      RECT 57.888 6.816 57.912 6.840 ;
    END
  END wd_in[98]
  PIN wd_in[99]
    DIRECTION INPUT ;
    USE SIGNAL ;
    SHAPE ABUTMENT ;
    PORT
      LAYER M4 ;
      RECT 57.888 7.104 57.912 7.128 ;
    END
  END wd_in[99]
  PIN wd_in[100]
    DIRECTION INPUT ;
    USE SIGNAL ;
    SHAPE ABUTMENT ;
    PORT
      LAYER M4 ;
      RECT 57.888 7.392 57.912 7.416 ;
    END
  END wd_in[100]
  PIN wd_in[101]
    DIRECTION INPUT ;
    USE SIGNAL ;
    SHAPE ABUTMENT ;
    PORT
      LAYER M4 ;
      RECT 57.888 7.680 57.912 7.704 ;
    END
  END wd_in[101]
  PIN wd_in[102]
    DIRECTION INPUT ;
    USE SIGNAL ;
    SHAPE ABUTMENT ;
    PORT
      LAYER M4 ;
      RECT 57.888 7.968 57.912 7.992 ;
    END
  END wd_in[102]
  PIN wd_in[103]
    DIRECTION INPUT ;
    USE SIGNAL ;
    SHAPE ABUTMENT ;
    PORT
      LAYER M4 ;
      RECT 57.888 8.256 57.912 8.280 ;
    END
  END wd_in[103]
  PIN wd_in[104]
    DIRECTION INPUT ;
    USE SIGNAL ;
    SHAPE ABUTMENT ;
    PORT
      LAYER M4 ;
      RECT 57.888 8.544 57.912 8.568 ;
    END
  END wd_in[104]
  PIN wd_in[105]
    DIRECTION INPUT ;
    USE SIGNAL ;
    SHAPE ABUTMENT ;
    PORT
      LAYER M4 ;
      RECT 57.888 8.832 57.912 8.856 ;
    END
  END wd_in[105]
  PIN wd_in[106]
    DIRECTION INPUT ;
    USE SIGNAL ;
    SHAPE ABUTMENT ;
    PORT
      LAYER M4 ;
      RECT 57.888 9.120 57.912 9.144 ;
    END
  END wd_in[106]
  PIN wd_in[107]
    DIRECTION INPUT ;
    USE SIGNAL ;
    SHAPE ABUTMENT ;
    PORT
      LAYER M4 ;
      RECT 57.888 9.408 57.912 9.432 ;
    END
  END wd_in[107]
  PIN wd_in[108]
    DIRECTION INPUT ;
    USE SIGNAL ;
    SHAPE ABUTMENT ;
    PORT
      LAYER M4 ;
      RECT 57.888 9.696 57.912 9.720 ;
    END
  END wd_in[108]
  PIN wd_in[109]
    DIRECTION INPUT ;
    USE SIGNAL ;
    SHAPE ABUTMENT ;
    PORT
      LAYER M4 ;
      RECT 57.888 9.984 57.912 10.008 ;
    END
  END wd_in[109]
  PIN wd_in[110]
    DIRECTION INPUT ;
    USE SIGNAL ;
    SHAPE ABUTMENT ;
    PORT
      LAYER M4 ;
      RECT 57.888 10.272 57.912 10.296 ;
    END
  END wd_in[110]
  PIN wd_in[111]
    DIRECTION INPUT ;
    USE SIGNAL ;
    SHAPE ABUTMENT ;
    PORT
      LAYER M4 ;
      RECT 57.888 10.560 57.912 10.584 ;
    END
  END wd_in[111]
  PIN wd_in[112]
    DIRECTION INPUT ;
    USE SIGNAL ;
    SHAPE ABUTMENT ;
    PORT
      LAYER M4 ;
      RECT 57.888 10.848 57.912 10.872 ;
    END
  END wd_in[112]
  PIN wd_in[113]
    DIRECTION INPUT ;
    USE SIGNAL ;
    SHAPE ABUTMENT ;
    PORT
      LAYER M4 ;
      RECT 57.888 11.136 57.912 11.160 ;
    END
  END wd_in[113]
  PIN wd_in[114]
    DIRECTION INPUT ;
    USE SIGNAL ;
    SHAPE ABUTMENT ;
    PORT
      LAYER M4 ;
      RECT 57.888 11.424 57.912 11.448 ;
    END
  END wd_in[114]
  PIN wd_in[115]
    DIRECTION INPUT ;
    USE SIGNAL ;
    SHAPE ABUTMENT ;
    PORT
      LAYER M4 ;
      RECT 57.888 11.712 57.912 11.736 ;
    END
  END wd_in[115]
  PIN wd_in[116]
    DIRECTION INPUT ;
    USE SIGNAL ;
    SHAPE ABUTMENT ;
    PORT
      LAYER M4 ;
      RECT 57.888 12.000 57.912 12.024 ;
    END
  END wd_in[116]
  PIN wd_in[117]
    DIRECTION INPUT ;
    USE SIGNAL ;
    SHAPE ABUTMENT ;
    PORT
      LAYER M4 ;
      RECT 57.888 12.288 57.912 12.312 ;
    END
  END wd_in[117]
  PIN wd_in[118]
    DIRECTION INPUT ;
    USE SIGNAL ;
    SHAPE ABUTMENT ;
    PORT
      LAYER M4 ;
      RECT 57.888 12.576 57.912 12.600 ;
    END
  END wd_in[118]
  PIN wd_in[119]
    DIRECTION INPUT ;
    USE SIGNAL ;
    SHAPE ABUTMENT ;
    PORT
      LAYER M4 ;
      RECT 57.888 12.864 57.912 12.888 ;
    END
  END wd_in[119]
  PIN wd_in[120]
    DIRECTION INPUT ;
    USE SIGNAL ;
    SHAPE ABUTMENT ;
    PORT
      LAYER M4 ;
      RECT 57.888 13.152 57.912 13.176 ;
    END
  END wd_in[120]
  PIN wd_in[121]
    DIRECTION INPUT ;
    USE SIGNAL ;
    SHAPE ABUTMENT ;
    PORT
      LAYER M4 ;
      RECT 57.888 13.440 57.912 13.464 ;
    END
  END wd_in[121]
  PIN wd_in[122]
    DIRECTION INPUT ;
    USE SIGNAL ;
    SHAPE ABUTMENT ;
    PORT
      LAYER M4 ;
      RECT 57.888 13.728 57.912 13.752 ;
    END
  END wd_in[122]
  PIN wd_in[123]
    DIRECTION INPUT ;
    USE SIGNAL ;
    SHAPE ABUTMENT ;
    PORT
      LAYER M4 ;
      RECT 57.888 14.016 57.912 14.040 ;
    END
  END wd_in[123]
  PIN wd_in[124]
    DIRECTION INPUT ;
    USE SIGNAL ;
    SHAPE ABUTMENT ;
    PORT
      LAYER M4 ;
      RECT 57.888 14.304 57.912 14.328 ;
    END
  END wd_in[124]
  PIN wd_in[125]
    DIRECTION INPUT ;
    USE SIGNAL ;
    SHAPE ABUTMENT ;
    PORT
      LAYER M4 ;
      RECT 57.888 14.592 57.912 14.616 ;
    END
  END wd_in[125]
  PIN wd_in[126]
    DIRECTION INPUT ;
    USE SIGNAL ;
    SHAPE ABUTMENT ;
    PORT
      LAYER M4 ;
      RECT 57.888 14.880 57.912 14.904 ;
    END
  END wd_in[126]
  PIN wd_in[127]
    DIRECTION INPUT ;
    USE SIGNAL ;
    SHAPE ABUTMENT ;
    PORT
      LAYER M4 ;
      RECT 57.888 15.168 57.912 15.192 ;
    END
  END wd_in[127]
  PIN wd_in[128]
    DIRECTION INPUT ;
    USE SIGNAL ;
    SHAPE ABUTMENT ;
    PORT
      LAYER M4 ;
      RECT 57.888 15.456 57.912 15.480 ;
    END
  END wd_in[128]
  PIN wd_in[129]
    DIRECTION INPUT ;
    USE SIGNAL ;
    SHAPE ABUTMENT ;
    PORT
      LAYER M4 ;
      RECT 57.888 15.744 57.912 15.768 ;
    END
  END wd_in[129]
  PIN wd_in[130]
    DIRECTION INPUT ;
    USE SIGNAL ;
    SHAPE ABUTMENT ;
    PORT
      LAYER M4 ;
      RECT 57.888 16.032 57.912 16.056 ;
    END
  END wd_in[130]
  PIN wd_in[131]
    DIRECTION INPUT ;
    USE SIGNAL ;
    SHAPE ABUTMENT ;
    PORT
      LAYER M4 ;
      RECT 57.888 16.320 57.912 16.344 ;
    END
  END wd_in[131]
  PIN wd_in[132]
    DIRECTION INPUT ;
    USE SIGNAL ;
    SHAPE ABUTMENT ;
    PORT
      LAYER M4 ;
      RECT 57.888 16.608 57.912 16.632 ;
    END
  END wd_in[132]
  PIN wd_in[133]
    DIRECTION INPUT ;
    USE SIGNAL ;
    SHAPE ABUTMENT ;
    PORT
      LAYER M4 ;
      RECT 57.888 16.896 57.912 16.920 ;
    END
  END wd_in[133]
  PIN wd_in[134]
    DIRECTION INPUT ;
    USE SIGNAL ;
    SHAPE ABUTMENT ;
    PORT
      LAYER M4 ;
      RECT 57.888 17.184 57.912 17.208 ;
    END
  END wd_in[134]
  PIN wd_in[135]
    DIRECTION INPUT ;
    USE SIGNAL ;
    SHAPE ABUTMENT ;
    PORT
      LAYER M4 ;
      RECT 57.888 17.472 57.912 17.496 ;
    END
  END wd_in[135]
  PIN wd_in[136]
    DIRECTION INPUT ;
    USE SIGNAL ;
    SHAPE ABUTMENT ;
    PORT
      LAYER M4 ;
      RECT 57.888 17.760 57.912 17.784 ;
    END
  END wd_in[136]
  PIN w_mask_in[0]
    DIRECTION INPUT ;
    USE SIGNAL ;
    SHAPE ABUTMENT ;
    PORT
      LAYER M4 ;
      RECT 57.888 18.048 57.912 18.072 ;
    END
  END w_mask_in[0]
  PIN w_mask_in[1]
    DIRECTION INPUT ;
    USE SIGNAL ;
    SHAPE ABUTMENT ;
    PORT
      LAYER M4 ;
      RECT 57.888 18.336 57.912 18.360 ;
    END
  END w_mask_in[1]
  PIN w_mask_in[2]
    DIRECTION INPUT ;
    USE SIGNAL ;
    SHAPE ABUTMENT ;
    PORT
      LAYER M4 ;
      RECT 57.888 18.624 57.912 18.648 ;
    END
  END w_mask_in[2]
  PIN w_mask_in[3]
    DIRECTION INPUT ;
    USE SIGNAL ;
    SHAPE ABUTMENT ;
    PORT
      LAYER M4 ;
      RECT 57.888 18.912 57.912 18.936 ;
    END
  END w_mask_in[3]
  PIN w_mask_in[4]
    DIRECTION INPUT ;
    USE SIGNAL ;
    SHAPE ABUTMENT ;
    PORT
      LAYER M4 ;
      RECT 57.888 19.200 57.912 19.224 ;
    END
  END w_mask_in[4]
  PIN w_mask_in[5]
    DIRECTION INPUT ;
    USE SIGNAL ;
    SHAPE ABUTMENT ;
    PORT
      LAYER M4 ;
      RECT 57.888 19.488 57.912 19.512 ;
    END
  END w_mask_in[5]
  PIN w_mask_in[6]
    DIRECTION INPUT ;
    USE SIGNAL ;
    SHAPE ABUTMENT ;
    PORT
      LAYER M4 ;
      RECT 57.888 19.776 57.912 19.800 ;
    END
  END w_mask_in[6]
  PIN w_mask_in[7]
    DIRECTION INPUT ;
    USE SIGNAL ;
    SHAPE ABUTMENT ;
    PORT
      LAYER M4 ;
      RECT 57.888 20.064 57.912 20.088 ;
    END
  END w_mask_in[7]
  PIN w_mask_in[8]
    DIRECTION INPUT ;
    USE SIGNAL ;
    SHAPE ABUTMENT ;
    PORT
      LAYER M4 ;
      RECT 57.888 20.352 57.912 20.376 ;
    END
  END w_mask_in[8]
  PIN w_mask_in[9]
    DIRECTION INPUT ;
    USE SIGNAL ;
    SHAPE ABUTMENT ;
    PORT
      LAYER M4 ;
      RECT 57.888 20.640 57.912 20.664 ;
    END
  END w_mask_in[9]
  PIN w_mask_in[10]
    DIRECTION INPUT ;
    USE SIGNAL ;
    SHAPE ABUTMENT ;
    PORT
      LAYER M4 ;
      RECT 57.888 20.928 57.912 20.952 ;
    END
  END w_mask_in[10]
  PIN w_mask_in[11]
    DIRECTION INPUT ;
    USE SIGNAL ;
    SHAPE ABUTMENT ;
    PORT
      LAYER M4 ;
      RECT 57.888 21.216 57.912 21.240 ;
    END
  END w_mask_in[11]
  PIN w_mask_in[12]
    DIRECTION INPUT ;
    USE SIGNAL ;
    SHAPE ABUTMENT ;
    PORT
      LAYER M4 ;
      RECT 57.888 21.504 57.912 21.528 ;
    END
  END w_mask_in[12]
  PIN w_mask_in[13]
    DIRECTION INPUT ;
    USE SIGNAL ;
    SHAPE ABUTMENT ;
    PORT
      LAYER M4 ;
      RECT 57.888 21.792 57.912 21.816 ;
    END
  END w_mask_in[13]
  PIN w_mask_in[14]
    DIRECTION INPUT ;
    USE SIGNAL ;
    SHAPE ABUTMENT ;
    PORT
      LAYER M4 ;
      RECT 57.888 22.080 57.912 22.104 ;
    END
  END w_mask_in[14]
  PIN w_mask_in[15]
    DIRECTION INPUT ;
    USE SIGNAL ;
    SHAPE ABUTMENT ;
    PORT
      LAYER M4 ;
      RECT 57.888 22.368 57.912 22.392 ;
    END
  END w_mask_in[15]
  PIN w_mask_in[16]
    DIRECTION INPUT ;
    USE SIGNAL ;
    SHAPE ABUTMENT ;
    PORT
      LAYER M4 ;
      RECT 57.888 22.656 57.912 22.680 ;
    END
  END w_mask_in[16]
  PIN w_mask_in[17]
    DIRECTION INPUT ;
    USE SIGNAL ;
    SHAPE ABUTMENT ;
    PORT
      LAYER M4 ;
      RECT 57.888 22.944 57.912 22.968 ;
    END
  END w_mask_in[17]
  PIN w_mask_in[18]
    DIRECTION INPUT ;
    USE SIGNAL ;
    SHAPE ABUTMENT ;
    PORT
      LAYER M4 ;
      RECT 57.888 23.232 57.912 23.256 ;
    END
  END w_mask_in[18]
  PIN w_mask_in[19]
    DIRECTION INPUT ;
    USE SIGNAL ;
    SHAPE ABUTMENT ;
    PORT
      LAYER M4 ;
      RECT 57.888 23.520 57.912 23.544 ;
    END
  END w_mask_in[19]
  PIN w_mask_in[20]
    DIRECTION INPUT ;
    USE SIGNAL ;
    SHAPE ABUTMENT ;
    PORT
      LAYER M4 ;
      RECT 57.888 23.808 57.912 23.832 ;
    END
  END w_mask_in[20]
  PIN w_mask_in[21]
    DIRECTION INPUT ;
    USE SIGNAL ;
    SHAPE ABUTMENT ;
    PORT
      LAYER M4 ;
      RECT 57.888 24.096 57.912 24.120 ;
    END
  END w_mask_in[21]
  PIN w_mask_in[22]
    DIRECTION INPUT ;
    USE SIGNAL ;
    SHAPE ABUTMENT ;
    PORT
      LAYER M4 ;
      RECT 57.888 24.384 57.912 24.408 ;
    END
  END w_mask_in[22]
  PIN w_mask_in[23]
    DIRECTION INPUT ;
    USE SIGNAL ;
    SHAPE ABUTMENT ;
    PORT
      LAYER M4 ;
      RECT 57.888 24.672 57.912 24.696 ;
    END
  END w_mask_in[23]
  PIN w_mask_in[24]
    DIRECTION INPUT ;
    USE SIGNAL ;
    SHAPE ABUTMENT ;
    PORT
      LAYER M4 ;
      RECT 57.888 24.960 57.912 24.984 ;
    END
  END w_mask_in[24]
  PIN w_mask_in[25]
    DIRECTION INPUT ;
    USE SIGNAL ;
    SHAPE ABUTMENT ;
    PORT
      LAYER M4 ;
      RECT 57.888 25.248 57.912 25.272 ;
    END
  END w_mask_in[25]
  PIN w_mask_in[26]
    DIRECTION INPUT ;
    USE SIGNAL ;
    SHAPE ABUTMENT ;
    PORT
      LAYER M4 ;
      RECT 57.888 25.536 57.912 25.560 ;
    END
  END w_mask_in[26]
  PIN w_mask_in[27]
    DIRECTION INPUT ;
    USE SIGNAL ;
    SHAPE ABUTMENT ;
    PORT
      LAYER M4 ;
      RECT 57.888 25.824 57.912 25.848 ;
    END
  END w_mask_in[27]
  PIN w_mask_in[28]
    DIRECTION INPUT ;
    USE SIGNAL ;
    SHAPE ABUTMENT ;
    PORT
      LAYER M4 ;
      RECT 57.888 26.112 57.912 26.136 ;
    END
  END w_mask_in[28]
  PIN w_mask_in[29]
    DIRECTION INPUT ;
    USE SIGNAL ;
    SHAPE ABUTMENT ;
    PORT
      LAYER M4 ;
      RECT 57.888 26.400 57.912 26.424 ;
    END
  END w_mask_in[29]
  PIN w_mask_in[30]
    DIRECTION INPUT ;
    USE SIGNAL ;
    SHAPE ABUTMENT ;
    PORT
      LAYER M4 ;
      RECT 57.888 26.688 57.912 26.712 ;
    END
  END w_mask_in[30]
  PIN w_mask_in[31]
    DIRECTION INPUT ;
    USE SIGNAL ;
    SHAPE ABUTMENT ;
    PORT
      LAYER M4 ;
      RECT 57.888 26.976 57.912 27.000 ;
    END
  END w_mask_in[31]
  PIN w_mask_in[32]
    DIRECTION INPUT ;
    USE SIGNAL ;
    SHAPE ABUTMENT ;
    PORT
      LAYER M4 ;
      RECT 57.888 27.264 57.912 27.288 ;
    END
  END w_mask_in[32]
  PIN w_mask_in[33]
    DIRECTION INPUT ;
    USE SIGNAL ;
    SHAPE ABUTMENT ;
    PORT
      LAYER M4 ;
      RECT 57.888 27.552 57.912 27.576 ;
    END
  END w_mask_in[33]
  PIN w_mask_in[34]
    DIRECTION INPUT ;
    USE SIGNAL ;
    SHAPE ABUTMENT ;
    PORT
      LAYER M4 ;
      RECT 57.888 27.840 57.912 27.864 ;
    END
  END w_mask_in[34]
  PIN w_mask_in[35]
    DIRECTION INPUT ;
    USE SIGNAL ;
    SHAPE ABUTMENT ;
    PORT
      LAYER M4 ;
      RECT 57.888 28.128 57.912 28.152 ;
    END
  END w_mask_in[35]
  PIN w_mask_in[36]
    DIRECTION INPUT ;
    USE SIGNAL ;
    SHAPE ABUTMENT ;
    PORT
      LAYER M4 ;
      RECT 57.888 28.416 57.912 28.440 ;
    END
  END w_mask_in[36]
  PIN w_mask_in[37]
    DIRECTION INPUT ;
    USE SIGNAL ;
    SHAPE ABUTMENT ;
    PORT
      LAYER M4 ;
      RECT 57.888 28.704 57.912 28.728 ;
    END
  END w_mask_in[37]
  PIN w_mask_in[38]
    DIRECTION INPUT ;
    USE SIGNAL ;
    SHAPE ABUTMENT ;
    PORT
      LAYER M4 ;
      RECT 57.888 28.992 57.912 29.016 ;
    END
  END w_mask_in[38]
  PIN w_mask_in[39]
    DIRECTION INPUT ;
    USE SIGNAL ;
    SHAPE ABUTMENT ;
    PORT
      LAYER M4 ;
      RECT 57.888 29.280 57.912 29.304 ;
    END
  END w_mask_in[39]
  PIN w_mask_in[40]
    DIRECTION INPUT ;
    USE SIGNAL ;
    SHAPE ABUTMENT ;
    PORT
      LAYER M4 ;
      RECT 57.888 29.568 57.912 29.592 ;
    END
  END w_mask_in[40]
  PIN w_mask_in[41]
    DIRECTION INPUT ;
    USE SIGNAL ;
    SHAPE ABUTMENT ;
    PORT
      LAYER M4 ;
      RECT 57.888 29.856 57.912 29.880 ;
    END
  END w_mask_in[41]
  PIN w_mask_in[42]
    DIRECTION INPUT ;
    USE SIGNAL ;
    SHAPE ABUTMENT ;
    PORT
      LAYER M4 ;
      RECT 57.888 30.144 57.912 30.168 ;
    END
  END w_mask_in[42]
  PIN w_mask_in[43]
    DIRECTION INPUT ;
    USE SIGNAL ;
    SHAPE ABUTMENT ;
    PORT
      LAYER M4 ;
      RECT 57.888 30.432 57.912 30.456 ;
    END
  END w_mask_in[43]
  PIN w_mask_in[44]
    DIRECTION INPUT ;
    USE SIGNAL ;
    SHAPE ABUTMENT ;
    PORT
      LAYER M4 ;
      RECT 57.888 30.720 57.912 30.744 ;
    END
  END w_mask_in[44]
  PIN w_mask_in[45]
    DIRECTION INPUT ;
    USE SIGNAL ;
    SHAPE ABUTMENT ;
    PORT
      LAYER M4 ;
      RECT 57.888 31.008 57.912 31.032 ;
    END
  END w_mask_in[45]
  PIN w_mask_in[46]
    DIRECTION INPUT ;
    USE SIGNAL ;
    SHAPE ABUTMENT ;
    PORT
      LAYER M4 ;
      RECT 57.888 31.296 57.912 31.320 ;
    END
  END w_mask_in[46]
  PIN w_mask_in[47]
    DIRECTION INPUT ;
    USE SIGNAL ;
    SHAPE ABUTMENT ;
    PORT
      LAYER M4 ;
      RECT 57.888 31.584 57.912 31.608 ;
    END
  END w_mask_in[47]
  PIN w_mask_in[48]
    DIRECTION INPUT ;
    USE SIGNAL ;
    SHAPE ABUTMENT ;
    PORT
      LAYER M4 ;
      RECT 57.888 31.872 57.912 31.896 ;
    END
  END w_mask_in[48]
  PIN w_mask_in[49]
    DIRECTION INPUT ;
    USE SIGNAL ;
    SHAPE ABUTMENT ;
    PORT
      LAYER M4 ;
      RECT 57.888 32.160 57.912 32.184 ;
    END
  END w_mask_in[49]
  PIN w_mask_in[50]
    DIRECTION INPUT ;
    USE SIGNAL ;
    SHAPE ABUTMENT ;
    PORT
      LAYER M4 ;
      RECT 57.888 32.448 57.912 32.472 ;
    END
  END w_mask_in[50]
  PIN w_mask_in[51]
    DIRECTION INPUT ;
    USE SIGNAL ;
    SHAPE ABUTMENT ;
    PORT
      LAYER M4 ;
      RECT 57.888 32.736 57.912 32.760 ;
    END
  END w_mask_in[51]
  PIN w_mask_in[52]
    DIRECTION INPUT ;
    USE SIGNAL ;
    SHAPE ABUTMENT ;
    PORT
      LAYER M4 ;
      RECT 57.888 33.024 57.912 33.048 ;
    END
  END w_mask_in[52]
  PIN w_mask_in[53]
    DIRECTION INPUT ;
    USE SIGNAL ;
    SHAPE ABUTMENT ;
    PORT
      LAYER M4 ;
      RECT 57.888 33.312 57.912 33.336 ;
    END
  END w_mask_in[53]
  PIN w_mask_in[54]
    DIRECTION INPUT ;
    USE SIGNAL ;
    SHAPE ABUTMENT ;
    PORT
      LAYER M4 ;
      RECT 57.888 33.600 57.912 33.624 ;
    END
  END w_mask_in[54]
  PIN w_mask_in[55]
    DIRECTION INPUT ;
    USE SIGNAL ;
    SHAPE ABUTMENT ;
    PORT
      LAYER M4 ;
      RECT 57.888 33.888 57.912 33.912 ;
    END
  END w_mask_in[55]
  PIN w_mask_in[56]
    DIRECTION INPUT ;
    USE SIGNAL ;
    SHAPE ABUTMENT ;
    PORT
      LAYER M4 ;
      RECT 57.888 34.176 57.912 34.200 ;
    END
  END w_mask_in[56]
  PIN w_mask_in[57]
    DIRECTION INPUT ;
    USE SIGNAL ;
    SHAPE ABUTMENT ;
    PORT
      LAYER M4 ;
      RECT 57.888 34.464 57.912 34.488 ;
    END
  END w_mask_in[57]
  PIN w_mask_in[58]
    DIRECTION INPUT ;
    USE SIGNAL ;
    SHAPE ABUTMENT ;
    PORT
      LAYER M4 ;
      RECT 57.888 34.752 57.912 34.776 ;
    END
  END w_mask_in[58]
  PIN w_mask_in[59]
    DIRECTION INPUT ;
    USE SIGNAL ;
    SHAPE ABUTMENT ;
    PORT
      LAYER M4 ;
      RECT 57.888 35.040 57.912 35.064 ;
    END
  END w_mask_in[59]
  PIN w_mask_in[60]
    DIRECTION INPUT ;
    USE SIGNAL ;
    SHAPE ABUTMENT ;
    PORT
      LAYER M4 ;
      RECT 57.888 35.328 57.912 35.352 ;
    END
  END w_mask_in[60]
  PIN w_mask_in[61]
    DIRECTION INPUT ;
    USE SIGNAL ;
    SHAPE ABUTMENT ;
    PORT
      LAYER M4 ;
      RECT 57.888 35.616 57.912 35.640 ;
    END
  END w_mask_in[61]
  PIN w_mask_in[62]
    DIRECTION INPUT ;
    USE SIGNAL ;
    SHAPE ABUTMENT ;
    PORT
      LAYER M4 ;
      RECT 57.888 35.904 57.912 35.928 ;
    END
  END w_mask_in[62]
  PIN w_mask_in[63]
    DIRECTION INPUT ;
    USE SIGNAL ;
    SHAPE ABUTMENT ;
    PORT
      LAYER M4 ;
      RECT 57.888 36.192 57.912 36.216 ;
    END
  END w_mask_in[63]
  PIN w_mask_in[64]
    DIRECTION INPUT ;
    USE SIGNAL ;
    SHAPE ABUTMENT ;
    PORT
      LAYER M4 ;
      RECT 57.888 36.480 57.912 36.504 ;
    END
  END w_mask_in[64]
  PIN w_mask_in[65]
    DIRECTION INPUT ;
    USE SIGNAL ;
    SHAPE ABUTMENT ;
    PORT
      LAYER M4 ;
      RECT 57.888 36.768 57.912 36.792 ;
    END
  END w_mask_in[65]
  PIN w_mask_in[66]
    DIRECTION INPUT ;
    USE SIGNAL ;
    SHAPE ABUTMENT ;
    PORT
      LAYER M4 ;
      RECT 57.888 37.056 57.912 37.080 ;
    END
  END w_mask_in[66]
  PIN w_mask_in[67]
    DIRECTION INPUT ;
    USE SIGNAL ;
    SHAPE ABUTMENT ;
    PORT
      LAYER M4 ;
      RECT 57.888 37.344 57.912 37.368 ;
    END
  END w_mask_in[67]
  PIN w_mask_in[68]
    DIRECTION INPUT ;
    USE SIGNAL ;
    SHAPE ABUTMENT ;
    PORT
      LAYER M4 ;
      RECT 57.888 37.632 57.912 37.656 ;
    END
  END w_mask_in[68]
  PIN w_mask_in[69]
    DIRECTION INPUT ;
    USE SIGNAL ;
    SHAPE ABUTMENT ;
    PORT
      LAYER M4 ;
      RECT 57.888 37.920 57.912 37.944 ;
    END
  END w_mask_in[69]
  PIN w_mask_in[70]
    DIRECTION INPUT ;
    USE SIGNAL ;
    SHAPE ABUTMENT ;
    PORT
      LAYER M4 ;
      RECT 57.888 38.208 57.912 38.232 ;
    END
  END w_mask_in[70]
  PIN w_mask_in[71]
    DIRECTION INPUT ;
    USE SIGNAL ;
    SHAPE ABUTMENT ;
    PORT
      LAYER M4 ;
      RECT 57.888 38.496 57.912 38.520 ;
    END
  END w_mask_in[71]
  PIN w_mask_in[72]
    DIRECTION INPUT ;
    USE SIGNAL ;
    SHAPE ABUTMENT ;
    PORT
      LAYER M4 ;
      RECT 57.888 38.784 57.912 38.808 ;
    END
  END w_mask_in[72]
  PIN w_mask_in[73]
    DIRECTION INPUT ;
    USE SIGNAL ;
    SHAPE ABUTMENT ;
    PORT
      LAYER M4 ;
      RECT 57.888 39.072 57.912 39.096 ;
    END
  END w_mask_in[73]
  PIN w_mask_in[74]
    DIRECTION INPUT ;
    USE SIGNAL ;
    SHAPE ABUTMENT ;
    PORT
      LAYER M4 ;
      RECT 57.888 39.360 57.912 39.384 ;
    END
  END w_mask_in[74]
  PIN w_mask_in[75]
    DIRECTION INPUT ;
    USE SIGNAL ;
    SHAPE ABUTMENT ;
    PORT
      LAYER M4 ;
      RECT 57.888 39.648 57.912 39.672 ;
    END
  END w_mask_in[75]
  PIN w_mask_in[76]
    DIRECTION INPUT ;
    USE SIGNAL ;
    SHAPE ABUTMENT ;
    PORT
      LAYER M4 ;
      RECT 57.888 39.936 57.912 39.960 ;
    END
  END w_mask_in[76]
  PIN w_mask_in[77]
    DIRECTION INPUT ;
    USE SIGNAL ;
    SHAPE ABUTMENT ;
    PORT
      LAYER M4 ;
      RECT 57.888 40.224 57.912 40.248 ;
    END
  END w_mask_in[77]
  PIN w_mask_in[78]
    DIRECTION INPUT ;
    USE SIGNAL ;
    SHAPE ABUTMENT ;
    PORT
      LAYER M4 ;
      RECT 57.888 40.512 57.912 40.536 ;
    END
  END w_mask_in[78]
  PIN w_mask_in[79]
    DIRECTION INPUT ;
    USE SIGNAL ;
    SHAPE ABUTMENT ;
    PORT
      LAYER M4 ;
      RECT 57.888 40.800 57.912 40.824 ;
    END
  END w_mask_in[79]
  PIN w_mask_in[80]
    DIRECTION INPUT ;
    USE SIGNAL ;
    SHAPE ABUTMENT ;
    PORT
      LAYER M4 ;
      RECT 57.888 41.088 57.912 41.112 ;
    END
  END w_mask_in[80]
  PIN w_mask_in[81]
    DIRECTION INPUT ;
    USE SIGNAL ;
    SHAPE ABUTMENT ;
    PORT
      LAYER M4 ;
      RECT 57.888 41.376 57.912 41.400 ;
    END
  END w_mask_in[81]
  PIN w_mask_in[82]
    DIRECTION INPUT ;
    USE SIGNAL ;
    SHAPE ABUTMENT ;
    PORT
      LAYER M4 ;
      RECT 57.888 41.664 57.912 41.688 ;
    END
  END w_mask_in[82]
  PIN w_mask_in[83]
    DIRECTION INPUT ;
    USE SIGNAL ;
    SHAPE ABUTMENT ;
    PORT
      LAYER M4 ;
      RECT 57.888 41.952 57.912 41.976 ;
    END
  END w_mask_in[83]
  PIN w_mask_in[84]
    DIRECTION INPUT ;
    USE SIGNAL ;
    SHAPE ABUTMENT ;
    PORT
      LAYER M4 ;
      RECT 57.888 42.240 57.912 42.264 ;
    END
  END w_mask_in[84]
  PIN w_mask_in[85]
    DIRECTION INPUT ;
    USE SIGNAL ;
    SHAPE ABUTMENT ;
    PORT
      LAYER M4 ;
      RECT 57.888 42.528 57.912 42.552 ;
    END
  END w_mask_in[85]
  PIN w_mask_in[86]
    DIRECTION INPUT ;
    USE SIGNAL ;
    SHAPE ABUTMENT ;
    PORT
      LAYER M4 ;
      RECT 57.888 42.816 57.912 42.840 ;
    END
  END w_mask_in[86]
  PIN w_mask_in[87]
    DIRECTION INPUT ;
    USE SIGNAL ;
    SHAPE ABUTMENT ;
    PORT
      LAYER M4 ;
      RECT 57.888 43.104 57.912 43.128 ;
    END
  END w_mask_in[87]
  PIN w_mask_in[88]
    DIRECTION INPUT ;
    USE SIGNAL ;
    SHAPE ABUTMENT ;
    PORT
      LAYER M4 ;
      RECT 57.888 43.392 57.912 43.416 ;
    END
  END w_mask_in[88]
  PIN w_mask_in[89]
    DIRECTION INPUT ;
    USE SIGNAL ;
    SHAPE ABUTMENT ;
    PORT
      LAYER M4 ;
      RECT 57.888 43.680 57.912 43.704 ;
    END
  END w_mask_in[89]
  PIN w_mask_in[90]
    DIRECTION INPUT ;
    USE SIGNAL ;
    SHAPE ABUTMENT ;
    PORT
      LAYER M4 ;
      RECT 57.888 43.968 57.912 43.992 ;
    END
  END w_mask_in[90]
  PIN w_mask_in[91]
    DIRECTION INPUT ;
    USE SIGNAL ;
    SHAPE ABUTMENT ;
    PORT
      LAYER M4 ;
      RECT 57.888 44.256 57.912 44.280 ;
    END
  END w_mask_in[91]
  PIN w_mask_in[92]
    DIRECTION INPUT ;
    USE SIGNAL ;
    SHAPE ABUTMENT ;
    PORT
      LAYER M4 ;
      RECT 57.888 44.544 57.912 44.568 ;
    END
  END w_mask_in[92]
  PIN w_mask_in[93]
    DIRECTION INPUT ;
    USE SIGNAL ;
    SHAPE ABUTMENT ;
    PORT
      LAYER M4 ;
      RECT 57.888 44.832 57.912 44.856 ;
    END
  END w_mask_in[93]
  PIN w_mask_in[94]
    DIRECTION INPUT ;
    USE SIGNAL ;
    SHAPE ABUTMENT ;
    PORT
      LAYER M4 ;
      RECT 57.888 45.120 57.912 45.144 ;
    END
  END w_mask_in[94]
  PIN w_mask_in[95]
    DIRECTION INPUT ;
    USE SIGNAL ;
    SHAPE ABUTMENT ;
    PORT
      LAYER M4 ;
      RECT 57.888 45.408 57.912 45.432 ;
    END
  END w_mask_in[95]
  PIN w_mask_in[96]
    DIRECTION INPUT ;
    USE SIGNAL ;
    SHAPE ABUTMENT ;
    PORT
      LAYER M4 ;
      RECT 57.888 45.696 57.912 45.720 ;
    END
  END w_mask_in[96]
  PIN w_mask_in[97]
    DIRECTION INPUT ;
    USE SIGNAL ;
    SHAPE ABUTMENT ;
    PORT
      LAYER M4 ;
      RECT 57.888 45.984 57.912 46.008 ;
    END
  END w_mask_in[97]
  PIN w_mask_in[98]
    DIRECTION INPUT ;
    USE SIGNAL ;
    SHAPE ABUTMENT ;
    PORT
      LAYER M4 ;
      RECT 57.888 46.272 57.912 46.296 ;
    END
  END w_mask_in[98]
  PIN w_mask_in[99]
    DIRECTION INPUT ;
    USE SIGNAL ;
    SHAPE ABUTMENT ;
    PORT
      LAYER M4 ;
      RECT 57.888 46.560 57.912 46.584 ;
    END
  END w_mask_in[99]
  PIN w_mask_in[100]
    DIRECTION INPUT ;
    USE SIGNAL ;
    SHAPE ABUTMENT ;
    PORT
      LAYER M4 ;
      RECT 57.888 46.848 57.912 46.872 ;
    END
  END w_mask_in[100]
  PIN w_mask_in[101]
    DIRECTION INPUT ;
    USE SIGNAL ;
    SHAPE ABUTMENT ;
    PORT
      LAYER M4 ;
      RECT 57.888 47.136 57.912 47.160 ;
    END
  END w_mask_in[101]
  PIN w_mask_in[102]
    DIRECTION INPUT ;
    USE SIGNAL ;
    SHAPE ABUTMENT ;
    PORT
      LAYER M4 ;
      RECT 57.888 47.424 57.912 47.448 ;
    END
  END w_mask_in[102]
  PIN w_mask_in[103]
    DIRECTION INPUT ;
    USE SIGNAL ;
    SHAPE ABUTMENT ;
    PORT
      LAYER M4 ;
      RECT 57.888 47.712 57.912 47.736 ;
    END
  END w_mask_in[103]
  PIN w_mask_in[104]
    DIRECTION INPUT ;
    USE SIGNAL ;
    SHAPE ABUTMENT ;
    PORT
      LAYER M4 ;
      RECT 57.888 48.000 57.912 48.024 ;
    END
  END w_mask_in[104]
  PIN w_mask_in[105]
    DIRECTION INPUT ;
    USE SIGNAL ;
    SHAPE ABUTMENT ;
    PORT
      LAYER M4 ;
      RECT 57.888 48.288 57.912 48.312 ;
    END
  END w_mask_in[105]
  PIN w_mask_in[106]
    DIRECTION INPUT ;
    USE SIGNAL ;
    SHAPE ABUTMENT ;
    PORT
      LAYER M4 ;
      RECT 57.888 48.576 57.912 48.600 ;
    END
  END w_mask_in[106]
  PIN w_mask_in[107]
    DIRECTION INPUT ;
    USE SIGNAL ;
    SHAPE ABUTMENT ;
    PORT
      LAYER M4 ;
      RECT 57.888 48.864 57.912 48.888 ;
    END
  END w_mask_in[107]
  PIN w_mask_in[108]
    DIRECTION INPUT ;
    USE SIGNAL ;
    SHAPE ABUTMENT ;
    PORT
      LAYER M4 ;
      RECT 57.888 49.152 57.912 49.176 ;
    END
  END w_mask_in[108]
  PIN w_mask_in[109]
    DIRECTION INPUT ;
    USE SIGNAL ;
    SHAPE ABUTMENT ;
    PORT
      LAYER M4 ;
      RECT 57.888 49.440 57.912 49.464 ;
    END
  END w_mask_in[109]
  PIN w_mask_in[110]
    DIRECTION INPUT ;
    USE SIGNAL ;
    SHAPE ABUTMENT ;
    PORT
      LAYER M4 ;
      RECT 57.888 49.728 57.912 49.752 ;
    END
  END w_mask_in[110]
  PIN w_mask_in[111]
    DIRECTION INPUT ;
    USE SIGNAL ;
    SHAPE ABUTMENT ;
    PORT
      LAYER M4 ;
      RECT 57.888 50.016 57.912 50.040 ;
    END
  END w_mask_in[111]
  PIN w_mask_in[112]
    DIRECTION INPUT ;
    USE SIGNAL ;
    SHAPE ABUTMENT ;
    PORT
      LAYER M4 ;
      RECT 57.888 50.304 57.912 50.328 ;
    END
  END w_mask_in[112]
  PIN w_mask_in[113]
    DIRECTION INPUT ;
    USE SIGNAL ;
    SHAPE ABUTMENT ;
    PORT
      LAYER M4 ;
      RECT 57.888 50.592 57.912 50.616 ;
    END
  END w_mask_in[113]
  PIN w_mask_in[114]
    DIRECTION INPUT ;
    USE SIGNAL ;
    SHAPE ABUTMENT ;
    PORT
      LAYER M4 ;
      RECT 57.888 50.880 57.912 50.904 ;
    END
  END w_mask_in[114]
  PIN w_mask_in[115]
    DIRECTION INPUT ;
    USE SIGNAL ;
    SHAPE ABUTMENT ;
    PORT
      LAYER M4 ;
      RECT 57.888 51.168 57.912 51.192 ;
    END
  END w_mask_in[115]
  PIN w_mask_in[116]
    DIRECTION INPUT ;
    USE SIGNAL ;
    SHAPE ABUTMENT ;
    PORT
      LAYER M4 ;
      RECT 57.888 51.456 57.912 51.480 ;
    END
  END w_mask_in[116]
  PIN w_mask_in[117]
    DIRECTION INPUT ;
    USE SIGNAL ;
    SHAPE ABUTMENT ;
    PORT
      LAYER M4 ;
      RECT 57.888 51.744 57.912 51.768 ;
    END
  END w_mask_in[117]
  PIN w_mask_in[118]
    DIRECTION INPUT ;
    USE SIGNAL ;
    SHAPE ABUTMENT ;
    PORT
      LAYER M4 ;
      RECT 57.888 52.032 57.912 52.056 ;
    END
  END w_mask_in[118]
  PIN w_mask_in[119]
    DIRECTION INPUT ;
    USE SIGNAL ;
    SHAPE ABUTMENT ;
    PORT
      LAYER M4 ;
      RECT 57.888 52.320 57.912 52.344 ;
    END
  END w_mask_in[119]
  PIN w_mask_in[120]
    DIRECTION INPUT ;
    USE SIGNAL ;
    SHAPE ABUTMENT ;
    PORT
      LAYER M4 ;
      RECT 57.888 52.608 57.912 52.632 ;
    END
  END w_mask_in[120]
  PIN w_mask_in[121]
    DIRECTION INPUT ;
    USE SIGNAL ;
    SHAPE ABUTMENT ;
    PORT
      LAYER M4 ;
      RECT 57.888 52.896 57.912 52.920 ;
    END
  END w_mask_in[121]
  PIN w_mask_in[122]
    DIRECTION INPUT ;
    USE SIGNAL ;
    SHAPE ABUTMENT ;
    PORT
      LAYER M4 ;
      RECT 57.888 53.184 57.912 53.208 ;
    END
  END w_mask_in[122]
  PIN w_mask_in[123]
    DIRECTION INPUT ;
    USE SIGNAL ;
    SHAPE ABUTMENT ;
    PORT
      LAYER M4 ;
      RECT 57.888 53.472 57.912 53.496 ;
    END
  END w_mask_in[123]
  PIN w_mask_in[124]
    DIRECTION INPUT ;
    USE SIGNAL ;
    SHAPE ABUTMENT ;
    PORT
      LAYER M4 ;
      RECT 57.888 53.760 57.912 53.784 ;
    END
  END w_mask_in[124]
  PIN w_mask_in[125]
    DIRECTION INPUT ;
    USE SIGNAL ;
    SHAPE ABUTMENT ;
    PORT
      LAYER M4 ;
      RECT 57.888 54.048 57.912 54.072 ;
    END
  END w_mask_in[125]
  PIN w_mask_in[126]
    DIRECTION INPUT ;
    USE SIGNAL ;
    SHAPE ABUTMENT ;
    PORT
      LAYER M4 ;
      RECT 57.888 54.336 57.912 54.360 ;
    END
  END w_mask_in[126]
  PIN w_mask_in[127]
    DIRECTION INPUT ;
    USE SIGNAL ;
    SHAPE ABUTMENT ;
    PORT
      LAYER M4 ;
      RECT 57.888 54.624 57.912 54.648 ;
    END
  END w_mask_in[127]
  PIN w_mask_in[128]
    DIRECTION INPUT ;
    USE SIGNAL ;
    SHAPE ABUTMENT ;
    PORT
      LAYER M4 ;
      RECT 57.888 54.912 57.912 54.936 ;
    END
  END w_mask_in[128]
  PIN w_mask_in[129]
    DIRECTION INPUT ;
    USE SIGNAL ;
    SHAPE ABUTMENT ;
    PORT
      LAYER M4 ;
      RECT 57.888 55.200 57.912 55.224 ;
    END
  END w_mask_in[129]
  PIN w_mask_in[130]
    DIRECTION INPUT ;
    USE SIGNAL ;
    SHAPE ABUTMENT ;
    PORT
      LAYER M4 ;
      RECT 57.888 55.488 57.912 55.512 ;
    END
  END w_mask_in[130]
  PIN w_mask_in[131]
    DIRECTION INPUT ;
    USE SIGNAL ;
    SHAPE ABUTMENT ;
    PORT
      LAYER M4 ;
      RECT 57.888 55.776 57.912 55.800 ;
    END
  END w_mask_in[131]
  PIN w_mask_in[132]
    DIRECTION INPUT ;
    USE SIGNAL ;
    SHAPE ABUTMENT ;
    PORT
      LAYER M4 ;
      RECT 57.888 56.064 57.912 56.088 ;
    END
  END w_mask_in[132]
  PIN w_mask_in[133]
    DIRECTION INPUT ;
    USE SIGNAL ;
    SHAPE ABUTMENT ;
    PORT
      LAYER M4 ;
      RECT 57.888 56.352 57.912 56.376 ;
    END
  END w_mask_in[133]
  PIN w_mask_in[134]
    DIRECTION INPUT ;
    USE SIGNAL ;
    SHAPE ABUTMENT ;
    PORT
      LAYER M4 ;
      RECT 57.888 56.640 57.912 56.664 ;
    END
  END w_mask_in[134]
  PIN w_mask_in[135]
    DIRECTION INPUT ;
    USE SIGNAL ;
    SHAPE ABUTMENT ;
    PORT
      LAYER M4 ;
      RECT 57.888 56.928 57.912 56.952 ;
    END
  END w_mask_in[135]
  PIN w_mask_in[136]
    DIRECTION INPUT ;
    USE SIGNAL ;
    SHAPE ABUTMENT ;
    PORT
      LAYER M4 ;
      RECT 57.888 57.216 57.912 57.240 ;
    END
  END w_mask_in[136]
  PIN rr_en[0]
    DIRECTION INPUT ;
    USE SIGNAL ;
    SHAPE ABUTMENT ;
    PORT
      LAYER M4 ;
      RECT 57.888 57.504 57.912 57.528 ;
    END
  END rr_en[0]
  PIN rr_en[1]
    DIRECTION INPUT ;
    USE SIGNAL ;
    SHAPE ABUTMENT ;
    PORT
      LAYER M4 ;
      RECT 57.888 57.792 57.912 57.816 ;
    END
  END rr_en[1]
  PIN rr_addr[0]
    DIRECTION INPUT ;
    USE SIGNAL ;
    SHAPE ABUTMENT ;
    PORT
      LAYER M4 ;
      RECT 57.888 58.080 57.912 58.104 ;
    END
  END rr_addr[0]
  PIN rr_addr[1]
    DIRECTION INPUT ;
    USE SIGNAL ;
    SHAPE ABUTMENT ;
    PORT
      LAYER M4 ;
      RECT 57.888 58.368 57.912 58.392 ;
    END
  END rr_addr[1]
  PIN rr_addr[2]
    DIRECTION INPUT ;
    USE SIGNAL ;
    SHAPE ABUTMENT ;
    PORT
      LAYER M4 ;
      RECT 57.888 58.656 57.912 58.680 ;
    END
  END rr_addr[2]
  PIN rr_addr[3]
    DIRECTION INPUT ;
    USE SIGNAL ;
    SHAPE ABUTMENT ;
    PORT
      LAYER M4 ;
      RECT 57.888 58.944 57.912 58.968 ;
    END
  END rr_addr[3]
  PIN rr_addr[4]
    DIRECTION INPUT ;
    USE SIGNAL ;
    SHAPE ABUTMENT ;
    PORT
      LAYER M4 ;
      RECT 57.888 59.232 57.912 59.256 ;
    END
  END rr_addr[4]
  PIN rr_addr[5]
    DIRECTION INPUT ;
    USE SIGNAL ;
    SHAPE ABUTMENT ;
    PORT
      LAYER M4 ;
      RECT 57.888 59.520 57.912 59.544 ;
    END
  END rr_addr[5]
  PIN rr_addr[6]
    DIRECTION INPUT ;
    USE SIGNAL ;
    SHAPE ABUTMENT ;
    PORT
      LAYER M4 ;
      RECT 57.888 59.808 57.912 59.832 ;
    END
  END rr_addr[6]
  PIN rr_addr[7]
    DIRECTION INPUT ;
    USE SIGNAL ;
    SHAPE ABUTMENT ;
    PORT
      LAYER M4 ;
      RECT 57.888 60.096 57.912 60.120 ;
    END
  END rr_addr[7]
  PIN rr_addr[8]
    DIRECTION INPUT ;
    USE SIGNAL ;
    SHAPE ABUTMENT ;
    PORT
      LAYER M4 ;
      RECT 57.888 60.384 57.912 60.408 ;
    END
  END rr_addr[8]
  PIN rr_addr[9]
    DIRECTION INPUT ;
    USE SIGNAL ;
    SHAPE ABUTMENT ;
    PORT
      LAYER M4 ;
      RECT 57.888 60.672 57.912 60.696 ;
    END
  END rr_addr[9]
  PIN rr_addr[10]
    DIRECTION INPUT ;
    USE SIGNAL ;
    SHAPE ABUTMENT ;
    PORT
      LAYER M4 ;
      RECT 57.888 60.960 57.912 60.984 ;
    END
  END rr_addr[10]
  PIN rr_addr[11]
    DIRECTION INPUT ;
    USE SIGNAL ;
    SHAPE ABUTMENT ;
    PORT
      LAYER M4 ;
      RECT 57.888 61.248 57.912 61.272 ;
    END
  END rr_addr[11]
  PIN cr_en[0]
    DIRECTION INPUT ;
    USE SIGNAL ;
    SHAPE ABUTMENT ;
    PORT
      LAYER M4 ;
      RECT 57.888 61.536 57.912 61.560 ;
    END
  END cr_en[0]
  PIN cr_en[1]
    DIRECTION INPUT ;
    USE SIGNAL ;
    SHAPE ABUTMENT ;
    PORT
      LAYER M4 ;
      RECT 57.888 61.824 57.912 61.848 ;
    END
  END cr_en[1]
  PIN cr_sel[0]
    DIRECTION INPUT ;
    USE SIGNAL ;
    SHAPE ABUTMENT ;
    PORT
      LAYER M4 ;
      RECT 57.888 62.112 57.912 62.136 ;
    END
  END cr_sel[0]
  PIN cr_sel[1]
    DIRECTION INPUT ;
    USE SIGNAL ;
    SHAPE ABUTMENT ;
    PORT
      LAYER M4 ;
      RECT 57.888 62.400 57.912 62.424 ;
    END
  END cr_sel[1]
  PIN cr_sel[2]
    DIRECTION INPUT ;
    USE SIGNAL ;
    SHAPE ABUTMENT ;
    PORT
      LAYER M4 ;
      RECT 57.888 62.688 57.912 62.712 ;
    END
  END cr_sel[2]
  PIN cr_sel[3]
    DIRECTION INPUT ;
    USE SIGNAL ;
    SHAPE ABUTMENT ;
    PORT
      LAYER M4 ;
      RECT 57.888 62.976 57.912 63.000 ;
    END
  END cr_sel[3]
  PIN cr_sel[4]
    DIRECTION INPUT ;
    USE SIGNAL ;
    SHAPE ABUTMENT ;
    PORT
      LAYER M4 ;
      RECT 57.888 63.264 57.912 63.288 ;
    END
  END cr_sel[4]
  PIN cr_sel[5]
    DIRECTION INPUT ;
    USE SIGNAL ;
    SHAPE ABUTMENT ;
    PORT
      LAYER M4 ;
      RECT 57.888 63.552 57.912 63.576 ;
    END
  END cr_sel[5]
  PIN cr_sel[6]
    DIRECTION INPUT ;
    USE SIGNAL ;
    SHAPE ABUTMENT ;
    PORT
      LAYER M4 ;
      RECT 57.888 63.840 57.912 63.864 ;
    END
  END cr_sel[6]
  PIN cr_sel[7]
    DIRECTION INPUT ;
    USE SIGNAL ;
    SHAPE ABUTMENT ;
    PORT
      LAYER M4 ;
      RECT 57.888 64.128 57.912 64.152 ;
    END
  END cr_sel[7]
  PIN cr_sel[8]
    DIRECTION INPUT ;
    USE SIGNAL ;
    SHAPE ABUTMENT ;
    PORT
      LAYER M4 ;
      RECT 57.888 64.416 57.912 64.440 ;
    END
  END cr_sel[8]
  PIN cr_sel[9]
    DIRECTION INPUT ;
    USE SIGNAL ;
    SHAPE ABUTMENT ;
    PORT
      LAYER M4 ;
      RECT 57.888 64.704 57.912 64.728 ;
    END
  END cr_sel[9]
  PIN cr_sel[10]
    DIRECTION INPUT ;
    USE SIGNAL ;
    SHAPE ABUTMENT ;
    PORT
      LAYER M4 ;
      RECT 57.888 64.992 57.912 65.016 ;
    END
  END cr_sel[10]
  PIN cr_sel[11]
    DIRECTION INPUT ;
    USE SIGNAL ;
    SHAPE ABUTMENT ;
    PORT
      LAYER M4 ;
      RECT 57.888 65.280 57.912 65.304 ;
    END
  END cr_sel[11]
  PIN cr_sel[12]
    DIRECTION INPUT ;
    USE SIGNAL ;
    SHAPE ABUTMENT ;
    PORT
      LAYER M4 ;
      RECT 57.888 65.568 57.912 65.592 ;
    END
  END cr_sel[12]
  PIN cr_sel[13]
    DIRECTION INPUT ;
    USE SIGNAL ;
    SHAPE ABUTMENT ;
    PORT
      LAYER M4 ;
      RECT 57.888 65.856 57.912 65.880 ;
    END
  END cr_sel[13]
  PIN cr_sel[14]
    DIRECTION INPUT ;
    USE SIGNAL ;
    SHAPE ABUTMENT ;
    PORT
      LAYER M4 ;
      RECT 57.888 66.144 57.912 66.168 ;
    END
  END cr_sel[14]
  PIN cr_sel[15]
    DIRECTION INPUT ;
    USE SIGNAL ;
    SHAPE ABUTMENT ;
    PORT
      LAYER M4 ;
      RECT 57.888 66.432 57.912 66.456 ;
    END
  END cr_sel[15]
  PIN VDD
    DIRECTION INOUT ;
    USE POWER ;
    PORT
      LAYER M4 ;
      RECT 0.300 0.384 57.612 0.480 ;
      RECT 0.300 1.152 57.612 1.248 ;
      RECT 0.300 1.920 57.612 2.016 ;
      RECT 0.300 2.688 57.612 2.784 ;
      RECT 0.300 3.456 57.612 3.552 ;
      RECT 0.300 4.224 57.612 4.320 ;
      RECT 0.300 4.992 57.612 5.088 ;
      RECT 0.300 5.760 57.612 5.856 ;
      RECT 0.300 6.528 57.612 6.624 ;
      RECT 0.300 7.296 57.612 7.392 ;
      RECT 0.300 8.064 57.612 8.160 ;
      RECT 0.300 8.832 57.612 8.928 ;
      RECT 0.300 9.600 57.612 9.696 ;
      RECT 0.300 10.368 57.612 10.464 ;
      RECT 0.300 11.136 57.612 11.232 ;
      RECT 0.300 11.904 57.612 12.000 ;
      RECT 0.300 12.672 57.612 12.768 ;
      RECT 0.300 13.440 57.612 13.536 ;
      RECT 0.300 14.208 57.612 14.304 ;
      RECT 0.300 14.976 57.612 15.072 ;
      RECT 0.300 15.744 57.612 15.840 ;
      RECT 0.300 16.512 57.612 16.608 ;
      RECT 0.300 17.280 57.612 17.376 ;
      RECT 0.300 18.048 57.612 18.144 ;
      RECT 0.300 18.816 57.612 18.912 ;
      RECT 0.300 19.584 57.612 19.680 ;
      RECT 0.300 20.352 57.612 20.448 ;
      RECT 0.300 21.120 57.612 21.216 ;
      RECT 0.300 21.888 57.612 21.984 ;
      RECT 0.300 22.656 57.612 22.752 ;
      RECT 0.300 23.424 57.612 23.520 ;
      RECT 0.300 24.192 57.612 24.288 ;
      RECT 0.300 24.960 57.612 25.056 ;
      RECT 0.300 25.728 57.612 25.824 ;
      RECT 0.300 26.496 57.612 26.592 ;
      RECT 0.300 27.264 57.612 27.360 ;
      RECT 0.300 28.032 57.612 28.128 ;
      RECT 0.300 28.800 57.612 28.896 ;
      RECT 0.300 29.568 57.612 29.664 ;
      RECT 0.300 30.336 57.612 30.432 ;
      RECT 0.300 31.104 57.612 31.200 ;
      RECT 0.300 31.872 57.612 31.968 ;
      RECT 0.300 32.640 57.612 32.736 ;
      RECT 0.300 33.408 57.612 33.504 ;
      RECT 0.300 34.176 57.612 34.272 ;
      RECT 0.300 34.944 57.612 35.040 ;
      RECT 0.300 35.712 57.612 35.808 ;
      RECT 0.300 36.480 57.612 36.576 ;
      RECT 0.300 37.248 57.612 37.344 ;
      RECT 0.300 38.016 57.612 38.112 ;
      RECT 0.300 38.784 57.612 38.880 ;
      RECT 0.300 39.552 57.612 39.648 ;
      RECT 0.300 40.320 57.612 40.416 ;
      RECT 0.300 41.088 57.612 41.184 ;
      RECT 0.300 41.856 57.612 41.952 ;
      RECT 0.300 42.624 57.612 42.720 ;
      RECT 0.300 43.392 57.612 43.488 ;
      RECT 0.300 44.160 57.612 44.256 ;
      RECT 0.300 44.928 57.612 45.024 ;
      RECT 0.300 45.696 57.612 45.792 ;
      RECT 0.300 46.464 57.612 46.560 ;
      RECT 0.300 47.232 57.612 47.328 ;
      RECT 0.300 48.000 57.612 48.096 ;
      RECT 0.300 48.768 57.612 48.864 ;
      RECT 0.300 49.536 57.612 49.632 ;
      RECT 0.300 50.304 57.612 50.400 ;
      RECT 0.300 51.072 57.612 51.168 ;
      RECT 0.300 51.840 57.612 51.936 ;
      RECT 0.300 52.608 57.612 52.704 ;
      RECT 0.300 53.376 57.612 53.472 ;
      RECT 0.300 54.144 57.612 54.240 ;
      RECT 0.300 54.912 57.612 55.008 ;
      RECT 0.300 55.680 57.612 55.776 ;
      RECT 0.300 56.448 57.612 56.544 ;
      RECT 0.300 57.216 57.612 57.312 ;
      RECT 0.300 57.984 57.612 58.080 ;
      RECT 0.300 58.752 57.612 58.848 ;
      RECT 0.300 59.520 57.612 59.616 ;
      RECT 0.300 60.288 57.612 60.384 ;
      RECT 0.300 61.056 57.612 61.152 ;
      RECT 0.300 61.824 57.612 61.920 ;
      RECT 0.300 62.592 57.612 62.688 ;
      RECT 0.300 63.360 57.612 63.456 ;
      RECT 0.300 64.128 57.612 64.224 ;
      RECT 0.300 64.896 57.612 64.992 ;
      RECT 0.300 65.664 57.612 65.760 ;
      RECT 0.300 66.432 57.612 66.528 ;
      RECT 0.300 67.200 57.612 67.296 ;
    END
  END VDD
  PIN VSS
    DIRECTION INOUT ;
    USE GROUND ;
    PORT
      LAYER M4 ;
      RECT 0.300 0.768 57.612 0.864 ;
      RECT 0.300 1.536 57.612 1.632 ;
      RECT 0.300 2.304 57.612 2.400 ;
      RECT 0.300 3.072 57.612 3.168 ;
      RECT 0.300 3.840 57.612 3.936 ;
      RECT 0.300 4.608 57.612 4.704 ;
      RECT 0.300 5.376 57.612 5.472 ;
      RECT 0.300 6.144 57.612 6.240 ;
      RECT 0.300 6.912 57.612 7.008 ;
      RECT 0.300 7.680 57.612 7.776 ;
      RECT 0.300 8.448 57.612 8.544 ;
      RECT 0.300 9.216 57.612 9.312 ;
      RECT 0.300 9.984 57.612 10.080 ;
      RECT 0.300 10.752 57.612 10.848 ;
      RECT 0.300 11.520 57.612 11.616 ;
      RECT 0.300 12.288 57.612 12.384 ;
      RECT 0.300 13.056 57.612 13.152 ;
      RECT 0.300 13.824 57.612 13.920 ;
      RECT 0.300 14.592 57.612 14.688 ;
      RECT 0.300 15.360 57.612 15.456 ;
      RECT 0.300 16.128 57.612 16.224 ;
      RECT 0.300 16.896 57.612 16.992 ;
      RECT 0.300 17.664 57.612 17.760 ;
      RECT 0.300 18.432 57.612 18.528 ;
      RECT 0.300 19.200 57.612 19.296 ;
      RECT 0.300 19.968 57.612 20.064 ;
      RECT 0.300 20.736 57.612 20.832 ;
      RECT 0.300 21.504 57.612 21.600 ;
      RECT 0.300 22.272 57.612 22.368 ;
      RECT 0.300 23.040 57.612 23.136 ;
      RECT 0.300 23.808 57.612 23.904 ;
      RECT 0.300 24.576 57.612 24.672 ;
      RECT 0.300 25.344 57.612 25.440 ;
      RECT 0.300 26.112 57.612 26.208 ;
      RECT 0.300 26.880 57.612 26.976 ;
      RECT 0.300 27.648 57.612 27.744 ;
      RECT 0.300 28.416 57.612 28.512 ;
      RECT 0.300 29.184 57.612 29.280 ;
      RECT 0.300 29.952 57.612 30.048 ;
      RECT 0.300 30.720 57.612 30.816 ;
      RECT 0.300 31.488 57.612 31.584 ;
      RECT 0.300 32.256 57.612 32.352 ;
      RECT 0.300 33.024 57.612 33.120 ;
      RECT 0.300 33.792 57.612 33.888 ;
      RECT 0.300 34.560 57.612 34.656 ;
      RECT 0.300 35.328 57.612 35.424 ;
      RECT 0.300 36.096 57.612 36.192 ;
      RECT 0.300 36.864 57.612 36.960 ;
      RECT 0.300 37.632 57.612 37.728 ;
      RECT 0.300 38.400 57.612 38.496 ;
      RECT 0.300 39.168 57.612 39.264 ;
      RECT 0.300 39.936 57.612 40.032 ;
      RECT 0.300 40.704 57.612 40.800 ;
      RECT 0.300 41.472 57.612 41.568 ;
      RECT 0.300 42.240 57.612 42.336 ;
      RECT 0.300 43.008 57.612 43.104 ;
      RECT 0.300 43.776 57.612 43.872 ;
      RECT 0.300 44.544 57.612 44.640 ;
      RECT 0.300 45.312 57.612 45.408 ;
      RECT 0.300 46.080 57.612 46.176 ;
      RECT 0.300 46.848 57.612 46.944 ;
      RECT 0.300 47.616 57.612 47.712 ;
      RECT 0.300 48.384 57.612 48.480 ;
      RECT 0.300 49.152 57.612 49.248 ;
      RECT 0.300 49.920 57.612 50.016 ;
      RECT 0.300 50.688 57.612 50.784 ;
      RECT 0.300 51.456 57.612 51.552 ;
      RECT 0.300 52.224 57.612 52.320 ;
      RECT 0.300 52.992 57.612 53.088 ;
      RECT 0.300 53.760 57.612 53.856 ;
      RECT 0.300 54.528 57.612 54.624 ;
      RECT 0.300 55.296 57.612 55.392 ;
      RECT 0.300 56.064 57.612 56.160 ;
      RECT 0.300 56.832 57.612 56.928 ;
      RECT 0.300 57.600 57.612 57.696 ;
      RECT 0.300 58.368 57.612 58.464 ;
      RECT 0.300 59.136 57.612 59.232 ;
      RECT 0.300 59.904 57.612 60.000 ;
      RECT 0.300 60.672 57.612 60.768 ;
      RECT 0.300 61.440 57.612 61.536 ;
      RECT 0.300 62.208 57.612 62.304 ;
      RECT 0.300 62.976 57.612 63.072 ;
      RECT 0.300 63.744 57.612 63.840 ;
      RECT 0.300 64.512 57.612 64.608 ;
      RECT 0.300 65.280 57.612 65.376 ;
      RECT 0.300 66.048 57.612 66.144 ;
      RECT 0.300 66.816 57.612 66.912 ;
    END
  END VSS
  OBS
    LAYER M1 ;
    RECT 0 0 57.912 67.512 ;
    LAYER M2 ;
    RECT 0 0 57.912 67.512 ;
    LAYER M3 ;
    RECT 0 0 57.912 67.512 ;
    LAYER M4 ;
    RECT 0.072 0 57.840 67.512 ;
  END
END d2d_sram_1r1w_64x137_m1_r2c2_p288

END LIBRARY
